VERSION 5.8 ;
BUSBITCHARS "[]" ;
DIVIDERCHAR "/" ;
UNITS
    DATABASE MICRONS 1000 ;
END UNITS

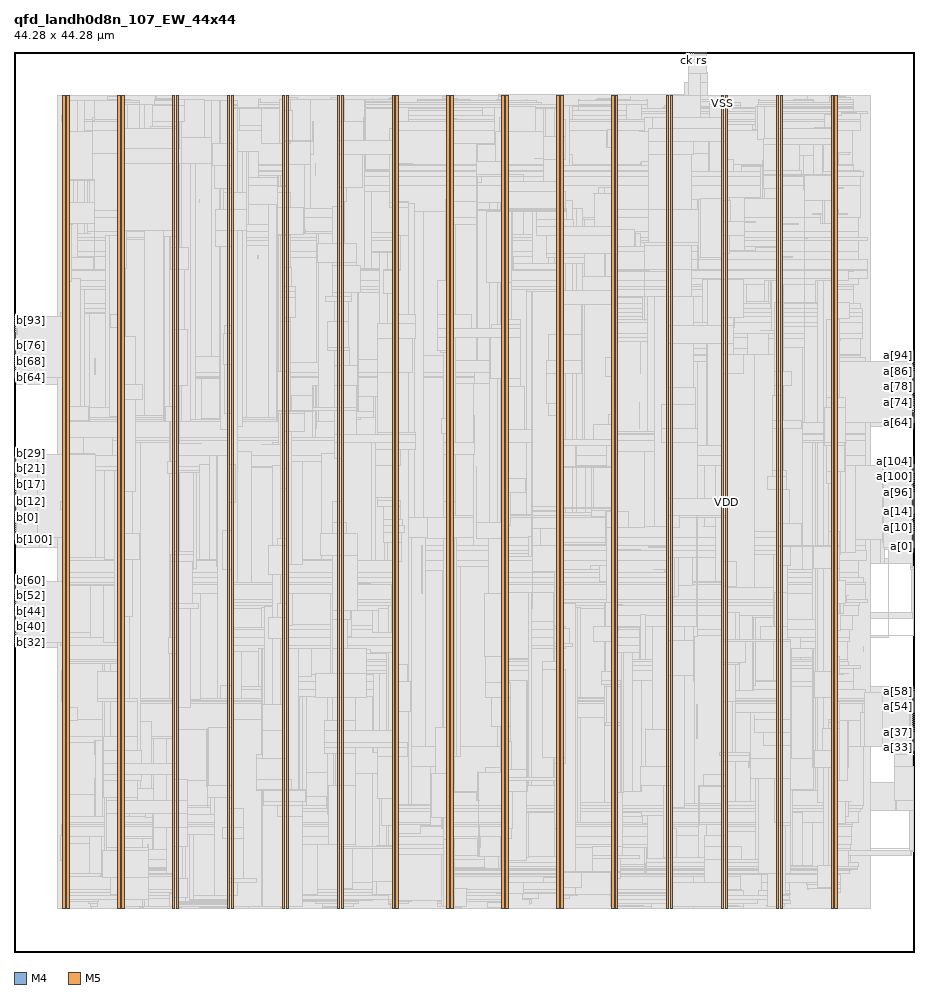
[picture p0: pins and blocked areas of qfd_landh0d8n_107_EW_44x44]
MACRO qfd_landh0d8n_107_EW_44x44
  FOREIGN qfd_landh0d8n_107_EW_44x44 0 0 ;
  CLASS BLOCK ;
  SIZE 44.28 BY 44.28 ;
  PIN a[0]
    DIRECTION INPUT ;
    USE SIGNAL ;
    PORT
      LAYER M4 ;
        RECT  44.196 19.92 44.28 19.944 ;
    END
  END a[0]
  PIN a[100]
    DIRECTION INPUT ;
    USE SIGNAL ;
    PORT
      LAYER M4 ;
        RECT  44.196 23.376 44.28 23.4 ;
    END
  END a[100]
  PIN a[101]
    DIRECTION INPUT ;
    USE SIGNAL ;
    PORT
      LAYER M4 ;
        RECT  44.196 23.472 44.28 23.496 ;
    END
  END a[101]
  PIN a[102]
    DIRECTION INPUT ;
    USE SIGNAL ;
    PORT
      LAYER M4 ;
        RECT  44.196 23.568 44.28 23.592 ;
    END
  END a[102]
  PIN a[103]
    DIRECTION INPUT ;
    USE SIGNAL ;
    PORT
      LAYER M4 ;
        RECT  44.196 23.664 44.28 23.688 ;
    END
  END a[103]
  PIN a[104]
    DIRECTION INPUT ;
    USE SIGNAL ;
    PORT
      LAYER M4 ;
        RECT  44.196 23.76 44.28 23.784 ;
    END
  END a[104]
  PIN a[105]
    DIRECTION INPUT ;
    USE SIGNAL ;
    PORT
      LAYER M4 ;
        RECT  44.196 23.856 44.28 23.88 ;
    END
  END a[105]
  PIN a[106]
    DIRECTION INPUT ;
    USE SIGNAL ;
    PORT
      LAYER M4 ;
        RECT  44.196 23.952 44.28 23.976 ;
    END
  END a[106]
  PIN a[10]
    DIRECTION INPUT ;
    USE SIGNAL ;
    PORT
      LAYER M4 ;
        RECT  44.196 20.88 44.28 20.904 ;
    END
  END a[10]
  PIN a[11]
    DIRECTION INPUT ;
    USE SIGNAL ;
    PORT
      LAYER M4 ;
        RECT  44.196 20.976 44.28 21 ;
    END
  END a[11]
  PIN a[12]
    DIRECTION INPUT ;
    USE SIGNAL ;
    PORT
      LAYER M4 ;
        RECT  44.196 21.072 44.28 21.096 ;
    END
  END a[12]
  PIN a[13]
    DIRECTION INPUT ;
    USE SIGNAL ;
    PORT
      LAYER M4 ;
        RECT  44.196 21.168 44.28 21.192 ;
    END
  END a[13]
  PIN a[14]
    DIRECTION INPUT ;
    USE SIGNAL ;
    PORT
      LAYER M4 ;
        RECT  44.196 21.264 44.28 21.288 ;
    END
  END a[14]
  PIN a[15]
    DIRECTION INPUT ;
    USE SIGNAL ;
    PORT
      LAYER M4 ;
        RECT  44.196 21.36 44.28 21.384 ;
    END
  END a[15]
  PIN a[16]
    DIRECTION INPUT ;
    USE SIGNAL ;
    PORT
      LAYER M4 ;
        RECT  44.196 21.456 44.28 21.48 ;
    END
  END a[16]
  PIN a[17]
    DIRECTION INPUT ;
    USE SIGNAL ;
    PORT
      LAYER M4 ;
        RECT  44.196 21.552 44.28 21.576 ;
    END
  END a[17]
  PIN a[18]
    DIRECTION INPUT ;
    USE SIGNAL ;
    PORT
      LAYER M4 ;
        RECT  44.196 21.648 44.28 21.672 ;
    END
  END a[18]
  PIN a[19]
    DIRECTION INPUT ;
    USE SIGNAL ;
    PORT
      LAYER M4 ;
        RECT  44.196 21.744 44.28 21.768 ;
    END
  END a[19]
  PIN a[1]
    DIRECTION INPUT ;
    USE SIGNAL ;
    PORT
      LAYER M4 ;
        RECT  44.196 20.016 44.28 20.04 ;
    END
  END a[1]
  PIN a[20]
    DIRECTION INPUT ;
    USE SIGNAL ;
    PORT
      LAYER M4 ;
        RECT  44.196 21.84 44.28 21.864 ;
    END
  END a[20]
  PIN a[21]
    DIRECTION INPUT ;
    USE SIGNAL ;
    PORT
      LAYER M4 ;
        RECT  44.196 21.936 44.28 21.96 ;
    END
  END a[21]
  PIN a[22]
    DIRECTION INPUT ;
    USE SIGNAL ;
    PORT
      LAYER M4 ;
        RECT  44.196 22.032 44.28 22.056 ;
    END
  END a[22]
  PIN a[23]
    DIRECTION INPUT ;
    USE SIGNAL ;
    PORT
      LAYER M4 ;
        RECT  44.196 22.128 44.28 22.152 ;
    END
  END a[23]
  PIN a[24]
    DIRECTION INPUT ;
    USE SIGNAL ;
    PORT
      LAYER M4 ;
        RECT  44.196 22.224 44.28 22.248 ;
    END
  END a[24]
  PIN a[25]
    DIRECTION INPUT ;
    USE SIGNAL ;
    PORT
      LAYER M4 ;
        RECT  44.196 22.32 44.28 22.344 ;
    END
  END a[25]
  PIN a[26]
    DIRECTION INPUT ;
    USE SIGNAL ;
    PORT
      LAYER M4 ;
        RECT  44.196 22.416 44.28 22.44 ;
    END
  END a[26]
  PIN a[27]
    DIRECTION INPUT ;
    USE SIGNAL ;
    PORT
      LAYER M4 ;
        RECT  44.196 22.512 44.28 22.536 ;
    END
  END a[27]
  PIN a[28]
    DIRECTION INPUT ;
    USE SIGNAL ;
    PORT
      LAYER M4 ;
        RECT  44.196 22.608 44.28 22.632 ;
    END
  END a[28]
  PIN a[29]
    DIRECTION INPUT ;
    USE SIGNAL ;
    PORT
      LAYER M4 ;
        RECT  44.196 22.704 44.28 22.728 ;
    END
  END a[29]
  PIN a[2]
    DIRECTION INPUT ;
    USE SIGNAL ;
    PORT
      LAYER M4 ;
        RECT  44.196 20.112 44.28 20.136 ;
    END
  END a[2]
  PIN a[30]
    DIRECTION INPUT ;
    USE SIGNAL ;
    PORT
      LAYER M4 ;
        RECT  44.196 22.8 44.28 22.824 ;
    END
  END a[30]
  PIN a[31]
    DIRECTION INPUT ;
    USE SIGNAL ;
    PORT
      LAYER M4 ;
        RECT  44.196 22.896 44.28 22.92 ;
    END
  END a[31]
  PIN a[32]
    DIRECTION INPUT ;
    USE SIGNAL ;
    PORT
      LAYER M4 ;
        RECT  44.196 9.936 44.28 9.96 ;
    END
  END a[32]
  PIN a[33]
    DIRECTION INPUT ;
    USE SIGNAL ;
    PORT
      LAYER M4 ;
        RECT  44.196 10.032 44.28 10.056 ;
    END
  END a[33]
  PIN a[34]
    DIRECTION INPUT ;
    USE SIGNAL ;
    PORT
      LAYER M4 ;
        RECT  44.196 10.128 44.28 10.152 ;
    END
  END a[34]
  PIN a[35]
    DIRECTION INPUT ;
    USE SIGNAL ;
    PORT
      LAYER M4 ;
        RECT  44.196 10.224 44.28 10.248 ;
    END
  END a[35]
  PIN a[36]
    DIRECTION INPUT ;
    USE SIGNAL ;
    PORT
      LAYER M4 ;
        RECT  44.196 10.32 44.28 10.344 ;
    END
  END a[36]
  PIN a[37]
    DIRECTION INPUT ;
    USE SIGNAL ;
    PORT
      LAYER M4 ;
        RECT  44.196 10.416 44.28 10.44 ;
    END
  END a[37]
  PIN a[38]
    DIRECTION INPUT ;
    USE SIGNAL ;
    PORT
      LAYER M4 ;
        RECT  44.196 10.512 44.28 10.536 ;
    END
  END a[38]
  PIN a[39]
    DIRECTION INPUT ;
    USE SIGNAL ;
    PORT
      LAYER M4 ;
        RECT  44.196 10.608 44.28 10.632 ;
    END
  END a[39]
  PIN a[3]
    DIRECTION INPUT ;
    USE SIGNAL ;
    PORT
      LAYER M4 ;
        RECT  44.196 20.208 44.28 20.232 ;
    END
  END a[3]
  PIN a[40]
    DIRECTION INPUT ;
    USE SIGNAL ;
    PORT
      LAYER M4 ;
        RECT  44.196 10.704 44.28 10.728 ;
    END
  END a[40]
  PIN a[41]
    DIRECTION INPUT ;
    USE SIGNAL ;
    PORT
      LAYER M4 ;
        RECT  44.196 10.8 44.28 10.824 ;
    END
  END a[41]
  PIN a[42]
    DIRECTION INPUT ;
    USE SIGNAL ;
    PORT
      LAYER M4 ;
        RECT  44.196 10.896 44.28 10.92 ;
    END
  END a[42]
  PIN a[43]
    DIRECTION INPUT ;
    USE SIGNAL ;
    PORT
      LAYER M4 ;
        RECT  44.196 10.992 44.28 11.016 ;
    END
  END a[43]
  PIN a[44]
    DIRECTION INPUT ;
    USE SIGNAL ;
    PORT
      LAYER M4 ;
        RECT  44.196 11.088 44.28 11.112 ;
    END
  END a[44]
  PIN a[45]
    DIRECTION INPUT ;
    USE SIGNAL ;
    PORT
      LAYER M4 ;
        RECT  44.196 11.184 44.28 11.208 ;
    END
  END a[45]
  PIN a[46]
    DIRECTION INPUT ;
    USE SIGNAL ;
    PORT
      LAYER M4 ;
        RECT  44.196 11.28 44.28 11.304 ;
    END
  END a[46]
  PIN a[47]
    DIRECTION INPUT ;
    USE SIGNAL ;
    PORT
      LAYER M4 ;
        RECT  44.196 11.376 44.28 11.4 ;
    END
  END a[47]
  PIN a[48]
    DIRECTION INPUT ;
    USE SIGNAL ;
    PORT
      LAYER M4 ;
        RECT  44.196 11.472 44.28 11.496 ;
    END
  END a[48]
  PIN a[49]
    DIRECTION INPUT ;
    USE SIGNAL ;
    PORT
      LAYER M4 ;
        RECT  44.196 11.568 44.28 11.592 ;
    END
  END a[49]
  PIN a[4]
    DIRECTION INPUT ;
    USE SIGNAL ;
    PORT
      LAYER M4 ;
        RECT  44.196 20.304 44.28 20.328 ;
    END
  END a[4]
  PIN a[50]
    DIRECTION INPUT ;
    USE SIGNAL ;
    PORT
      LAYER M4 ;
        RECT  44.196 11.664 44.28 11.688 ;
    END
  END a[50]
  PIN a[51]
    DIRECTION INPUT ;
    USE SIGNAL ;
    PORT
      LAYER M4 ;
        RECT  44.196 11.76 44.28 11.784 ;
    END
  END a[51]
  PIN a[52]
    DIRECTION INPUT ;
    USE SIGNAL ;
    PORT
      LAYER M4 ;
        RECT  44.196 11.856 44.28 11.88 ;
    END
  END a[52]
  PIN a[53]
    DIRECTION INPUT ;
    USE SIGNAL ;
    PORT
      LAYER M4 ;
        RECT  44.196 11.952 44.28 11.976 ;
    END
  END a[53]
  PIN a[54]
    DIRECTION INPUT ;
    USE SIGNAL ;
    PORT
      LAYER M4 ;
        RECT  44.196 12.048 44.28 12.072 ;
    END
  END a[54]
  PIN a[55]
    DIRECTION INPUT ;
    USE SIGNAL ;
    PORT
      LAYER M4 ;
        RECT  44.196 12.144 44.28 12.168 ;
    END
  END a[55]
  PIN a[56]
    DIRECTION INPUT ;
    USE SIGNAL ;
    PORT
      LAYER M4 ;
        RECT  44.196 12.24 44.28 12.264 ;
    END
  END a[56]
  PIN a[57]
    DIRECTION INPUT ;
    USE SIGNAL ;
    PORT
      LAYER M4 ;
        RECT  44.196 12.336 44.28 12.36 ;
    END
  END a[57]
  PIN a[58]
    DIRECTION INPUT ;
    USE SIGNAL ;
    PORT
      LAYER M4 ;
        RECT  44.196 12.432 44.28 12.456 ;
    END
  END a[58]
  PIN a[59]
    DIRECTION INPUT ;
    USE SIGNAL ;
    PORT
      LAYER M4 ;
        RECT  44.196 12.528 44.28 12.552 ;
    END
  END a[59]
  PIN a[5]
    DIRECTION INPUT ;
    USE SIGNAL ;
    PORT
      LAYER M4 ;
        RECT  44.196 20.4 44.28 20.424 ;
    END
  END a[5]
  PIN a[60]
    DIRECTION INPUT ;
    USE SIGNAL ;
    PORT
      LAYER M4 ;
        RECT  44.196 12.624 44.28 12.648 ;
    END
  END a[60]
  PIN a[61]
    DIRECTION INPUT ;
    USE SIGNAL ;
    PORT
      LAYER M4 ;
        RECT  44.196 12.72 44.28 12.744 ;
    END
  END a[61]
  PIN a[62]
    DIRECTION INPUT ;
    USE SIGNAL ;
    PORT
      LAYER M4 ;
        RECT  44.196 12.816 44.28 12.84 ;
    END
  END a[62]
  PIN a[63]
    DIRECTION INPUT ;
    USE SIGNAL ;
    PORT
      LAYER M4 ;
        RECT  44.196 12.912 44.28 12.936 ;
    END
  END a[63]
  PIN a[64]
    DIRECTION INPUT ;
    USE SIGNAL ;
    PORT
      LAYER M4 ;
        RECT  44.196 26.064 44.28 26.088 ;
    END
  END a[64]
  PIN a[65]
    DIRECTION INPUT ;
    USE SIGNAL ;
    PORT
      LAYER M4 ;
        RECT  44.196 26.16 44.28 26.184 ;
    END
  END a[65]
  PIN a[66]
    DIRECTION INPUT ;
    USE SIGNAL ;
    PORT
      LAYER M4 ;
        RECT  44.196 26.256 44.28 26.28 ;
    END
  END a[66]
  PIN a[67]
    DIRECTION INPUT ;
    USE SIGNAL ;
    PORT
      LAYER M4 ;
        RECT  44.196 26.352 44.28 26.376 ;
    END
  END a[67]
  PIN a[68]
    DIRECTION INPUT ;
    USE SIGNAL ;
    PORT
      LAYER M4 ;
        RECT  44.196 26.448 44.28 26.472 ;
    END
  END a[68]
  PIN a[69]
    DIRECTION INPUT ;
    USE SIGNAL ;
    PORT
      LAYER M4 ;
        RECT  44.196 26.544 44.28 26.568 ;
    END
  END a[69]
  PIN a[6]
    DIRECTION INPUT ;
    USE SIGNAL ;
    PORT
      LAYER M4 ;
        RECT  44.196 20.496 44.28 20.52 ;
    END
  END a[6]
  PIN a[70]
    DIRECTION INPUT ;
    USE SIGNAL ;
    PORT
      LAYER M4 ;
        RECT  44.196 26.64 44.28 26.664 ;
    END
  END a[70]
  PIN a[71]
    DIRECTION INPUT ;
    USE SIGNAL ;
    PORT
      LAYER M4 ;
        RECT  44.196 26.736 44.28 26.76 ;
    END
  END a[71]
  PIN a[72]
    DIRECTION INPUT ;
    USE SIGNAL ;
    PORT
      LAYER M4 ;
        RECT  44.196 26.832 44.28 26.856 ;
    END
  END a[72]
  PIN a[73]
    DIRECTION INPUT ;
    USE SIGNAL ;
    PORT
      LAYER M4 ;
        RECT  44.196 26.928 44.28 26.952 ;
    END
  END a[73]
  PIN a[74]
    DIRECTION INPUT ;
    USE SIGNAL ;
    PORT
      LAYER M4 ;
        RECT  44.196 27.024 44.28 27.048 ;
    END
  END a[74]
  PIN a[75]
    DIRECTION INPUT ;
    USE SIGNAL ;
    PORT
      LAYER M4 ;
        RECT  44.196 27.12 44.28 27.144 ;
    END
  END a[75]
  PIN a[76]
    DIRECTION INPUT ;
    USE SIGNAL ;
    PORT
      LAYER M4 ;
        RECT  44.196 27.216 44.28 27.24 ;
    END
  END a[76]
  PIN a[77]
    DIRECTION INPUT ;
    USE SIGNAL ;
    PORT
      LAYER M4 ;
        RECT  44.196 27.312 44.28 27.336 ;
    END
  END a[77]
  PIN a[78]
    DIRECTION INPUT ;
    USE SIGNAL ;
    PORT
      LAYER M4 ;
        RECT  44.196 27.408 44.28 27.432 ;
    END
  END a[78]
  PIN a[79]
    DIRECTION INPUT ;
    USE SIGNAL ;
    PORT
      LAYER M4 ;
        RECT  44.196 27.504 44.28 27.528 ;
    END
  END a[79]
  PIN a[7]
    DIRECTION INPUT ;
    USE SIGNAL ;
    PORT
      LAYER M4 ;
        RECT  44.196 20.592 44.28 20.616 ;
    END
  END a[7]
  PIN a[80]
    DIRECTION INPUT ;
    USE SIGNAL ;
    PORT
      LAYER M4 ;
        RECT  44.196 27.6 44.28 27.624 ;
    END
  END a[80]
  PIN a[81]
    DIRECTION INPUT ;
    USE SIGNAL ;
    PORT
      LAYER M4 ;
        RECT  44.196 27.696 44.28 27.72 ;
    END
  END a[81]
  PIN a[82]
    DIRECTION INPUT ;
    USE SIGNAL ;
    PORT
      LAYER M4 ;
        RECT  44.196 27.792 44.28 27.816 ;
    END
  END a[82]
  PIN a[83]
    DIRECTION INPUT ;
    USE SIGNAL ;
    PORT
      LAYER M4 ;
        RECT  44.196 27.888 44.28 27.912 ;
    END
  END a[83]
  PIN a[84]
    DIRECTION INPUT ;
    USE SIGNAL ;
    PORT
      LAYER M4 ;
        RECT  44.196 27.984 44.28 28.008 ;
    END
  END a[84]
  PIN a[85]
    DIRECTION INPUT ;
    USE SIGNAL ;
    PORT
      LAYER M4 ;
        RECT  44.196 28.08 44.28 28.104 ;
    END
  END a[85]
  PIN a[86]
    DIRECTION INPUT ;
    USE SIGNAL ;
    PORT
      LAYER M4 ;
        RECT  44.196 28.176 44.28 28.2 ;
    END
  END a[86]
  PIN a[87]
    DIRECTION INPUT ;
    USE SIGNAL ;
    PORT
      LAYER M4 ;
        RECT  44.196 28.272 44.28 28.296 ;
    END
  END a[87]
  PIN a[88]
    DIRECTION INPUT ;
    USE SIGNAL ;
    PORT
      LAYER M4 ;
        RECT  44.196 28.368 44.28 28.392 ;
    END
  END a[88]
  PIN a[89]
    DIRECTION INPUT ;
    USE SIGNAL ;
    PORT
      LAYER M4 ;
        RECT  44.196 28.464 44.28 28.488 ;
    END
  END a[89]
  PIN a[8]
    DIRECTION INPUT ;
    USE SIGNAL ;
    PORT
      LAYER M4 ;
        RECT  44.196 20.688 44.28 20.712 ;
    END
  END a[8]
  PIN a[90]
    DIRECTION INPUT ;
    USE SIGNAL ;
    PORT
      LAYER M4 ;
        RECT  44.196 28.56 44.28 28.584 ;
    END
  END a[90]
  PIN a[91]
    DIRECTION INPUT ;
    USE SIGNAL ;
    PORT
      LAYER M4 ;
        RECT  44.196 28.656 44.28 28.68 ;
    END
  END a[91]
  PIN a[92]
    DIRECTION INPUT ;
    USE SIGNAL ;
    PORT
      LAYER M4 ;
        RECT  44.196 28.752 44.28 28.776 ;
    END
  END a[92]
  PIN a[93]
    DIRECTION INPUT ;
    USE SIGNAL ;
    PORT
      LAYER M4 ;
        RECT  44.196 28.848 44.28 28.872 ;
    END
  END a[93]
  PIN a[94]
    DIRECTION INPUT ;
    USE SIGNAL ;
    PORT
      LAYER M4 ;
        RECT  44.196 28.944 44.28 28.968 ;
    END
  END a[94]
  PIN a[95]
    DIRECTION INPUT ;
    USE SIGNAL ;
    PORT
      LAYER M4 ;
        RECT  44.196 29.04 44.28 29.064 ;
    END
  END a[95]
  PIN a[96]
    DIRECTION INPUT ;
    USE SIGNAL ;
    PORT
      LAYER M4 ;
        RECT  44.196 22.992 44.28 23.016 ;
    END
  END a[96]
  PIN a[97]
    DIRECTION INPUT ;
    USE SIGNAL ;
    PORT
      LAYER M4 ;
        RECT  44.196 23.088 44.28 23.112 ;
    END
  END a[97]
  PIN a[98]
    DIRECTION INPUT ;
    USE SIGNAL ;
    PORT
      LAYER M4 ;
        RECT  44.196 23.184 44.28 23.208 ;
    END
  END a[98]
  PIN a[99]
    DIRECTION INPUT ;
    USE SIGNAL ;
    PORT
      LAYER M4 ;
        RECT  44.196 23.28 44.28 23.304 ;
    END
  END a[99]
  PIN a[9]
    DIRECTION INPUT ;
    USE SIGNAL ;
    PORT
      LAYER M4 ;
        RECT  44.196 20.784 44.28 20.808 ;
    END
  END a[9]
  PIN b[0]
    DIRECTION OUTPUT ;
    USE SIGNAL ;
    PORT
      LAYER M4 ;
        RECT  0 21.36 0.084 21.384 ;
    END
  END b[0]
  PIN b[100]
    DIRECTION OUTPUT ;
    USE SIGNAL ;
    PORT
      LAYER M4 ;
        RECT  0 20.688 0.084 20.712 ;
    END
  END b[100]
  PIN b[101]
    DIRECTION OUTPUT ;
    USE SIGNAL ;
    PORT
      LAYER M4 ;
        RECT  0 20.784 0.084 20.808 ;
    END
  END b[101]
  PIN b[102]
    DIRECTION OUTPUT ;
    USE SIGNAL ;
    PORT
      LAYER M4 ;
        RECT  0 20.88 0.084 20.904 ;
    END
  END b[102]
  PIN b[103]
    DIRECTION OUTPUT ;
    USE SIGNAL ;
    PORT
      LAYER M4 ;
        RECT  0 20.976 0.084 21 ;
    END
  END b[103]
  PIN b[104]
    DIRECTION OUTPUT ;
    USE SIGNAL ;
    PORT
      LAYER M4 ;
        RECT  0 21.072 0.084 21.096 ;
    END
  END b[104]
  PIN b[105]
    DIRECTION OUTPUT ;
    USE SIGNAL ;
    PORT
      LAYER M4 ;
        RECT  0 21.168 0.084 21.192 ;
    END
  END b[105]
  PIN b[106]
    DIRECTION OUTPUT ;
    USE SIGNAL ;
    PORT
      LAYER M4 ;
        RECT  0 21.264 0.084 21.288 ;
    END
  END b[106]
  PIN b[10]
    DIRECTION OUTPUT ;
    USE SIGNAL ;
    PORT
      LAYER M4 ;
        RECT  0 22.32 0.084 22.344 ;
    END
  END b[10]
  PIN b[11]
    DIRECTION OUTPUT ;
    USE SIGNAL ;
    PORT
      LAYER M4 ;
        RECT  0 22.416 0.084 22.44 ;
    END
  END b[11]
  PIN b[12]
    DIRECTION OUTPUT ;
    USE SIGNAL ;
    PORT
      LAYER M4 ;
        RECT  0 22.512 0.084 22.536 ;
    END
  END b[12]
  PIN b[13]
    DIRECTION OUTPUT ;
    USE SIGNAL ;
    PORT
      LAYER M4 ;
        RECT  0 22.608 0.084 22.632 ;
    END
  END b[13]
  PIN b[14]
    DIRECTION OUTPUT ;
    USE SIGNAL ;
    PORT
      LAYER M4 ;
        RECT  0 22.704 0.084 22.728 ;
    END
  END b[14]
  PIN b[15]
    DIRECTION OUTPUT ;
    USE SIGNAL ;
    PORT
      LAYER M4 ;
        RECT  0 22.8 0.084 22.824 ;
    END
  END b[15]
  PIN b[16]
    DIRECTION OUTPUT ;
    USE SIGNAL ;
    PORT
      LAYER M4 ;
        RECT  0 22.896 0.084 22.92 ;
    END
  END b[16]
  PIN b[17]
    DIRECTION OUTPUT ;
    USE SIGNAL ;
    PORT
      LAYER M4 ;
        RECT  0 22.992 0.084 23.016 ;
    END
  END b[17]
  PIN b[18]
    DIRECTION OUTPUT ;
    USE SIGNAL ;
    PORT
      LAYER M4 ;
        RECT  0 23.088 0.084 23.112 ;
    END
  END b[18]
  PIN b[19]
    DIRECTION OUTPUT ;
    USE SIGNAL ;
    PORT
      LAYER M4 ;
        RECT  0 23.184 0.084 23.208 ;
    END
  END b[19]
  PIN b[1]
    DIRECTION OUTPUT ;
    USE SIGNAL ;
    PORT
      LAYER M4 ;
        RECT  0 21.456 0.084 21.48 ;
    END
  END b[1]
  PIN b[20]
    DIRECTION OUTPUT ;
    USE SIGNAL ;
    PORT
      LAYER M4 ;
        RECT  0 23.28 0.084 23.304 ;
    END
  END b[20]
  PIN b[21]
    DIRECTION OUTPUT ;
    USE SIGNAL ;
    PORT
      LAYER M4 ;
        RECT  0 23.376 0.084 23.4 ;
    END
  END b[21]
  PIN b[22]
    DIRECTION OUTPUT ;
    USE SIGNAL ;
    PORT
      LAYER M4 ;
        RECT  0 23.472 0.084 23.496 ;
    END
  END b[22]
  PIN b[23]
    DIRECTION OUTPUT ;
    USE SIGNAL ;
    PORT
      LAYER M4 ;
        RECT  0 23.568 0.084 23.592 ;
    END
  END b[23]
  PIN b[24]
    DIRECTION OUTPUT ;
    USE SIGNAL ;
    PORT
      LAYER M4 ;
        RECT  0 23.664 0.084 23.688 ;
    END
  END b[24]
  PIN b[25]
    DIRECTION OUTPUT ;
    USE SIGNAL ;
    PORT
      LAYER M4 ;
        RECT  0 23.76 0.084 23.784 ;
    END
  END b[25]
  PIN b[26]
    DIRECTION OUTPUT ;
    USE SIGNAL ;
    PORT
      LAYER M4 ;
        RECT  0 23.856 0.084 23.88 ;
    END
  END b[26]
  PIN b[27]
    DIRECTION OUTPUT ;
    USE SIGNAL ;
    PORT
      LAYER M4 ;
        RECT  0 23.952 0.084 23.976 ;
    END
  END b[27]
  PIN b[28]
    DIRECTION OUTPUT ;
    USE SIGNAL ;
    PORT
      LAYER M4 ;
        RECT  0 24.048 0.084 24.072 ;
    END
  END b[28]
  PIN b[29]
    DIRECTION OUTPUT ;
    USE SIGNAL ;
    PORT
      LAYER M4 ;
        RECT  0 24.144 0.084 24.168 ;
    END
  END b[29]
  PIN b[2]
    DIRECTION OUTPUT ;
    USE SIGNAL ;
    PORT
      LAYER M4 ;
        RECT  0 21.552 0.084 21.576 ;
    END
  END b[2]
  PIN b[30]
    DIRECTION OUTPUT ;
    USE SIGNAL ;
    PORT
      LAYER M4 ;
        RECT  0 24.24 0.084 24.264 ;
    END
  END b[30]
  PIN b[31]
    DIRECTION OUTPUT ;
    USE SIGNAL ;
    PORT
      LAYER M4 ;
        RECT  0 24.336 0.084 24.36 ;
    END
  END b[31]
  PIN b[32]
    DIRECTION OUTPUT ;
    USE SIGNAL ;
    PORT
      LAYER M4 ;
        RECT  0 15.216 0.084 15.24 ;
    END
  END b[32]
  PIN b[33]
    DIRECTION OUTPUT ;
    USE SIGNAL ;
    PORT
      LAYER M4 ;
        RECT  0 15.312 0.084 15.336 ;
    END
  END b[33]
  PIN b[34]
    DIRECTION OUTPUT ;
    USE SIGNAL ;
    PORT
      LAYER M4 ;
        RECT  0 15.408 0.084 15.432 ;
    END
  END b[34]
  PIN b[35]
    DIRECTION OUTPUT ;
    USE SIGNAL ;
    PORT
      LAYER M4 ;
        RECT  0 15.504 0.084 15.528 ;
    END
  END b[35]
  PIN b[36]
    DIRECTION OUTPUT ;
    USE SIGNAL ;
    PORT
      LAYER M4 ;
        RECT  0 15.6 0.084 15.624 ;
    END
  END b[36]
  PIN b[37]
    DIRECTION OUTPUT ;
    USE SIGNAL ;
    PORT
      LAYER M4 ;
        RECT  0 15.696 0.084 15.72 ;
    END
  END b[37]
  PIN b[38]
    DIRECTION OUTPUT ;
    USE SIGNAL ;
    PORT
      LAYER M4 ;
        RECT  0 15.792 0.084 15.816 ;
    END
  END b[38]
  PIN b[39]
    DIRECTION OUTPUT ;
    USE SIGNAL ;
    PORT
      LAYER M4 ;
        RECT  0 15.888 0.084 15.912 ;
    END
  END b[39]
  PIN b[3]
    DIRECTION OUTPUT ;
    USE SIGNAL ;
    PORT
      LAYER M4 ;
        RECT  0 21.648 0.084 21.672 ;
    END
  END b[3]
  PIN b[40]
    DIRECTION OUTPUT ;
    USE SIGNAL ;
    PORT
      LAYER M4 ;
        RECT  0 15.984 0.084 16.008 ;
    END
  END b[40]
  PIN b[41]
    DIRECTION OUTPUT ;
    USE SIGNAL ;
    PORT
      LAYER M4 ;
        RECT  0 16.08 0.084 16.104 ;
    END
  END b[41]
  PIN b[42]
    DIRECTION OUTPUT ;
    USE SIGNAL ;
    PORT
      LAYER M4 ;
        RECT  0 16.176 0.084 16.2 ;
    END
  END b[42]
  PIN b[43]
    DIRECTION OUTPUT ;
    USE SIGNAL ;
    PORT
      LAYER M4 ;
        RECT  0 16.272 0.084 16.296 ;
    END
  END b[43]
  PIN b[44]
    DIRECTION OUTPUT ;
    USE SIGNAL ;
    PORT
      LAYER M4 ;
        RECT  0 16.368 0.084 16.392 ;
    END
  END b[44]
  PIN b[45]
    DIRECTION OUTPUT ;
    USE SIGNAL ;
    PORT
      LAYER M4 ;
        RECT  0 16.464 0.084 16.488 ;
    END
  END b[45]
  PIN b[46]
    DIRECTION OUTPUT ;
    USE SIGNAL ;
    PORT
      LAYER M4 ;
        RECT  0 16.56 0.084 16.584 ;
    END
  END b[46]
  PIN b[47]
    DIRECTION OUTPUT ;
    USE SIGNAL ;
    PORT
      LAYER M4 ;
        RECT  0 16.656 0.084 16.68 ;
    END
  END b[47]
  PIN b[48]
    DIRECTION OUTPUT ;
    USE SIGNAL ;
    PORT
      LAYER M4 ;
        RECT  0 16.752 0.084 16.776 ;
    END
  END b[48]
  PIN b[49]
    DIRECTION OUTPUT ;
    USE SIGNAL ;
    PORT
      LAYER M4 ;
        RECT  0 16.848 0.084 16.872 ;
    END
  END b[49]
  PIN b[4]
    DIRECTION OUTPUT ;
    USE SIGNAL ;
    PORT
      LAYER M4 ;
        RECT  0 21.744 0.084 21.768 ;
    END
  END b[4]
  PIN b[50]
    DIRECTION OUTPUT ;
    USE SIGNAL ;
    PORT
      LAYER M4 ;
        RECT  0 16.944 0.084 16.968 ;
    END
  END b[50]
  PIN b[51]
    DIRECTION OUTPUT ;
    USE SIGNAL ;
    PORT
      LAYER M4 ;
        RECT  0 17.04 0.084 17.064 ;
    END
  END b[51]
  PIN b[52]
    DIRECTION OUTPUT ;
    USE SIGNAL ;
    PORT
      LAYER M4 ;
        RECT  0 17.136 0.084 17.16 ;
    END
  END b[52]
  PIN b[53]
    DIRECTION OUTPUT ;
    USE SIGNAL ;
    PORT
      LAYER M4 ;
        RECT  0 17.232 0.084 17.256 ;
    END
  END b[53]
  PIN b[54]
    DIRECTION OUTPUT ;
    USE SIGNAL ;
    PORT
      LAYER M4 ;
        RECT  0 17.328 0.084 17.352 ;
    END
  END b[54]
  PIN b[55]
    DIRECTION OUTPUT ;
    USE SIGNAL ;
    PORT
      LAYER M4 ;
        RECT  0 17.424 0.084 17.448 ;
    END
  END b[55]
  PIN b[56]
    DIRECTION OUTPUT ;
    USE SIGNAL ;
    PORT
      LAYER M4 ;
        RECT  0 17.52 0.084 17.544 ;
    END
  END b[56]
  PIN b[57]
    DIRECTION OUTPUT ;
    USE SIGNAL ;
    PORT
      LAYER M4 ;
        RECT  0 17.616 0.084 17.64 ;
    END
  END b[57]
  PIN b[58]
    DIRECTION OUTPUT ;
    USE SIGNAL ;
    PORT
      LAYER M4 ;
        RECT  0 17.712 0.084 17.736 ;
    END
  END b[58]
  PIN b[59]
    DIRECTION OUTPUT ;
    USE SIGNAL ;
    PORT
      LAYER M4 ;
        RECT  0 17.808 0.084 17.832 ;
    END
  END b[59]
  PIN b[5]
    DIRECTION OUTPUT ;
    USE SIGNAL ;
    PORT
      LAYER M4 ;
        RECT  0 21.84 0.084 21.864 ;
    END
  END b[5]
  PIN b[60]
    DIRECTION OUTPUT ;
    USE SIGNAL ;
    PORT
      LAYER M4 ;
        RECT  0 17.904 0.084 17.928 ;
    END
  END b[60]
  PIN b[61]
    DIRECTION OUTPUT ;
    USE SIGNAL ;
    PORT
      LAYER M4 ;
        RECT  0 18 0.084 18.024 ;
    END
  END b[61]
  PIN b[62]
    DIRECTION OUTPUT ;
    USE SIGNAL ;
    PORT
      LAYER M4 ;
        RECT  0 18.096 0.084 18.12 ;
    END
  END b[62]
  PIN b[63]
    DIRECTION OUTPUT ;
    USE SIGNAL ;
    PORT
      LAYER M4 ;
        RECT  0 18.192 0.084 18.216 ;
    END
  END b[63]
  PIN b[64]
    DIRECTION OUTPUT ;
    USE SIGNAL ;
    PORT
      LAYER M4 ;
        RECT  0 28.272 0.084 28.296 ;
    END
  END b[64]
  PIN b[65]
    DIRECTION OUTPUT ;
    USE SIGNAL ;
    PORT
      LAYER M4 ;
        RECT  0 28.368 0.084 28.392 ;
    END
  END b[65]
  PIN b[66]
    DIRECTION OUTPUT ;
    USE SIGNAL ;
    PORT
      LAYER M4 ;
        RECT  0 28.464 0.084 28.488 ;
    END
  END b[66]
  PIN b[67]
    DIRECTION OUTPUT ;
    USE SIGNAL ;
    PORT
      LAYER M4 ;
        RECT  0 28.56 0.084 28.584 ;
    END
  END b[67]
  PIN b[68]
    DIRECTION OUTPUT ;
    USE SIGNAL ;
    PORT
      LAYER M4 ;
        RECT  0 28.656 0.084 28.68 ;
    END
  END b[68]
  PIN b[69]
    DIRECTION OUTPUT ;
    USE SIGNAL ;
    PORT
      LAYER M4 ;
        RECT  0 28.752 0.084 28.776 ;
    END
  END b[69]
  PIN b[6]
    DIRECTION OUTPUT ;
    USE SIGNAL ;
    PORT
      LAYER M4 ;
        RECT  0 21.936 0.084 21.96 ;
    END
  END b[6]
  PIN b[70]
    DIRECTION OUTPUT ;
    USE SIGNAL ;
    PORT
      LAYER M4 ;
        RECT  0 28.848 0.084 28.872 ;
    END
  END b[70]
  PIN b[71]
    DIRECTION OUTPUT ;
    USE SIGNAL ;
    PORT
      LAYER M4 ;
        RECT  0 28.944 0.084 28.968 ;
    END
  END b[71]
  PIN b[72]
    DIRECTION OUTPUT ;
    USE SIGNAL ;
    PORT
      LAYER M4 ;
        RECT  0 29.04 0.084 29.064 ;
    END
  END b[72]
  PIN b[73]
    DIRECTION OUTPUT ;
    USE SIGNAL ;
    PORT
      LAYER M4 ;
        RECT  0 29.136 0.084 29.16 ;
    END
  END b[73]
  PIN b[74]
    DIRECTION OUTPUT ;
    USE SIGNAL ;
    PORT
      LAYER M4 ;
        RECT  0 29.232 0.084 29.256 ;
    END
  END b[74]
  PIN b[75]
    DIRECTION OUTPUT ;
    USE SIGNAL ;
    PORT
      LAYER M4 ;
        RECT  0 29.328 0.084 29.352 ;
    END
  END b[75]
  PIN b[76]
    DIRECTION OUTPUT ;
    USE SIGNAL ;
    PORT
      LAYER M4 ;
        RECT  0 29.424 0.084 29.448 ;
    END
  END b[76]
  PIN b[77]
    DIRECTION OUTPUT ;
    USE SIGNAL ;
    PORT
      LAYER M4 ;
        RECT  0 29.52 0.084 29.544 ;
    END
  END b[77]
  PIN b[78]
    DIRECTION OUTPUT ;
    USE SIGNAL ;
    PORT
      LAYER M4 ;
        RECT  0 29.616 0.084 29.64 ;
    END
  END b[78]
  PIN b[79]
    DIRECTION OUTPUT ;
    USE SIGNAL ;
    PORT
      LAYER M4 ;
        RECT  0 29.712 0.084 29.736 ;
    END
  END b[79]
  PIN b[7]
    DIRECTION OUTPUT ;
    USE SIGNAL ;
    PORT
      LAYER M4 ;
        RECT  0 22.032 0.084 22.056 ;
    END
  END b[7]
  PIN b[80]
    DIRECTION OUTPUT ;
    USE SIGNAL ;
    PORT
      LAYER M4 ;
        RECT  0 29.808 0.084 29.832 ;
    END
  END b[80]
  PIN b[81]
    DIRECTION OUTPUT ;
    USE SIGNAL ;
    PORT
      LAYER M4 ;
        RECT  0 29.904 0.084 29.928 ;
    END
  END b[81]
  PIN b[82]
    DIRECTION OUTPUT ;
    USE SIGNAL ;
    PORT
      LAYER M4 ;
        RECT  0 30 0.084 30.024 ;
    END
  END b[82]
  PIN b[83]
    DIRECTION OUTPUT ;
    USE SIGNAL ;
    PORT
      LAYER M4 ;
        RECT  0 30.096 0.084 30.12 ;
    END
  END b[83]
  PIN b[84]
    DIRECTION OUTPUT ;
    USE SIGNAL ;
    PORT
      LAYER M4 ;
        RECT  0 30.192 0.084 30.216 ;
    END
  END b[84]
  PIN b[85]
    DIRECTION OUTPUT ;
    USE SIGNAL ;
    PORT
      LAYER M4 ;
        RECT  0 30.288 0.084 30.312 ;
    END
  END b[85]
  PIN b[86]
    DIRECTION OUTPUT ;
    USE SIGNAL ;
    PORT
      LAYER M4 ;
        RECT  0 30.384 0.084 30.408 ;
    END
  END b[86]
  PIN b[87]
    DIRECTION OUTPUT ;
    USE SIGNAL ;
    PORT
      LAYER M4 ;
        RECT  0 30.48 0.084 30.504 ;
    END
  END b[87]
  PIN b[88]
    DIRECTION OUTPUT ;
    USE SIGNAL ;
    PORT
      LAYER M4 ;
        RECT  0 30.576 0.084 30.6 ;
    END
  END b[88]
  PIN b[89]
    DIRECTION OUTPUT ;
    USE SIGNAL ;
    PORT
      LAYER M4 ;
        RECT  0 30.672 0.084 30.696 ;
    END
  END b[89]
  PIN b[8]
    DIRECTION OUTPUT ;
    USE SIGNAL ;
    PORT
      LAYER M4 ;
        RECT  0 22.128 0.084 22.152 ;
    END
  END b[8]
  PIN b[90]
    DIRECTION OUTPUT ;
    USE SIGNAL ;
    PORT
      LAYER M4 ;
        RECT  0 30.768 0.084 30.792 ;
    END
  END b[90]
  PIN b[91]
    DIRECTION OUTPUT ;
    USE SIGNAL ;
    PORT
      LAYER M4 ;
        RECT  0 30.864 0.084 30.888 ;
    END
  END b[91]
  PIN b[92]
    DIRECTION OUTPUT ;
    USE SIGNAL ;
    PORT
      LAYER M4 ;
        RECT  0 30.96 0.084 30.984 ;
    END
  END b[92]
  PIN b[93]
    DIRECTION OUTPUT ;
    USE SIGNAL ;
    PORT
      LAYER M4 ;
        RECT  0 31.056 0.084 31.08 ;
    END
  END b[93]
  PIN b[94]
    DIRECTION OUTPUT ;
    USE SIGNAL ;
    PORT
      LAYER M4 ;
        RECT  0 31.152 0.084 31.176 ;
    END
  END b[94]
  PIN b[95]
    DIRECTION OUTPUT ;
    USE SIGNAL ;
    PORT
      LAYER M4 ;
        RECT  0 31.248 0.084 31.272 ;
    END
  END b[95]
  PIN b[96]
    DIRECTION OUTPUT ;
    USE SIGNAL ;
    PORT
      LAYER M4 ;
        RECT  0 20.304 0.084 20.328 ;
    END
  END b[96]
  PIN b[97]
    DIRECTION OUTPUT ;
    USE SIGNAL ;
    PORT
      LAYER M4 ;
        RECT  0 20.4 0.084 20.424 ;
    END
  END b[97]
  PIN b[98]
    DIRECTION OUTPUT ;
    USE SIGNAL ;
    PORT
      LAYER M4 ;
        RECT  0 20.496 0.084 20.52 ;
    END
  END b[98]
  PIN b[99]
    DIRECTION OUTPUT ;
    USE SIGNAL ;
    PORT
      LAYER M4 ;
        RECT  0 20.592 0.084 20.616 ;
    END
  END b[99]
  PIN b[9]
    DIRECTION OUTPUT ;
    USE SIGNAL ;
    PORT
      LAYER M4 ;
        RECT  0 22.224 0.084 22.248 ;
    END
  END b[9]
  PIN ck
    DIRECTION INPUT ;
    USE SIGNAL ;
    PORT
      LAYER M5 ;
        RECT  33.072 44.196 33.096 44.28 ;
    END
  END ck
  PIN ck_s
    DIRECTION INPUT ;
    USE SIGNAL ;
    PORT
      LAYER M5 ;
        RECT  33.168 44.196 33.192 44.28 ;
    END
  END ck_s
  PIN en
    DIRECTION INPUT ;
    USE SIGNAL ;
    PORT
      LAYER M5 ;
        RECT  33.264 44.196 33.288 44.28 ;
    END
  END en
  PIN fault
    DIRECTION OUTPUT ;
    USE SIGNAL ;
    PORT
      LAYER M5 ;
        RECT  33.36 44.196 33.384 44.28 ;
    END
  END fault
  PIN k0
    DIRECTION INPUT ;
    USE SIGNAL ;
    PORT
      LAYER M5 ;
        RECT  33.456 44.196 33.48 44.28 ;
    END
  END k0
  PIN k1
    DIRECTION INPUT ;
    USE SIGNAL ;
    PORT
      LAYER M5 ;
        RECT  33.552 44.196 33.576 44.28 ;
    END
  END k1
  PIN k2
    DIRECTION INPUT ;
    USE SIGNAL ;
    PORT
      LAYER M5 ;
        RECT  33.648 44.196 33.672 44.28 ;
    END
  END k2
  PIN k3
    DIRECTION INPUT ;
    USE SIGNAL ;
    PORT
      LAYER M5 ;
        RECT  33.744 44.196 33.768 44.28 ;
    END
  END k3
  PIN rs
    DIRECTION INPUT ;
    USE SIGNAL ;
    PORT
      LAYER M5 ;
        RECT  33.84 44.196 33.864 44.28 ;
    END
  END rs
  PIN tie_hi
    DIRECTION OUTPUT ;
    USE SIGNAL ;
    PORT
      LAYER M5 ;
        RECT  33.936 44.196 33.96 44.28 ;
    END
  END tie_hi
  PIN tie_lo
    DIRECTION OUTPUT ;
    USE SIGNAL ;
    PORT
      LAYER M5 ;
        RECT  34.032 44.196 34.056 44.28 ;
    END
  END tie_lo
  PIN VSS
    DIRECTION INOUT ;
    USE GROUND ;
    PORT
      LAYER M5 ;
        RECT  40.2 2.137 40.32 42.143 ;
        RECT  37.5 2.137 37.62 42.143 ;
        RECT  34.8 2.137 34.92 42.143 ;
        RECT  32.1 2.137 32.22 42.143 ;
        RECT  29.4 2.137 29.52 42.143 ;
        RECT  26.7 2.137 26.82 42.143 ;
        RECT  24 2.137 24.12 42.143 ;
        RECT  21.3 2.137 21.42 42.143 ;
        RECT  18.6 2.137 18.72 42.143 ;
        RECT  15.9 2.137 16.02 42.143 ;
        RECT  13.2 2.137 13.32 42.143 ;
        RECT  10.5 2.137 10.62 42.143 ;
        RECT  7.8 2.137 7.92 42.143 ;
        RECT  5.1 2.137 5.22 42.143 ;
        RECT  2.4 2.137 2.52 42.143 ;
    END
  END VSS
  PIN VDD
    DIRECTION INOUT ;
    USE POWER ;
    PORT
      LAYER M5 ;
        RECT  40.392 2.151 40.512 42.129 ;
        RECT  37.692 2.151 37.812 42.129 ;
        RECT  34.992 2.151 35.112 42.129 ;
        RECT  32.292 2.151 32.412 42.129 ;
        RECT  29.592 2.151 29.712 42.129 ;
        RECT  26.892 2.151 27.012 42.129 ;
        RECT  24.192 2.151 24.312 42.129 ;
        RECT  21.492 2.151 21.612 42.129 ;
        RECT  18.792 2.151 18.912 42.129 ;
        RECT  16.092 2.151 16.212 42.129 ;
        RECT  13.392 2.151 13.512 42.129 ;
        RECT  10.692 2.151 10.812 42.129 ;
        RECT  7.992 2.151 8.112 42.129 ;
        RECT  5.292 2.151 5.412 42.129 ;
        RECT  2.592 2.151 2.712 42.129 ;
    END
  END VDD
  OBS
    LAYER RVTN ;
     RECT  2.16 2.16 42.12 2.295 ;
     RECT  2.16 2.565 42.12 2.835 ;
     RECT  2.16 3.105 42.12 3.375 ;
     RECT  2.16 3.645 42.12 3.915 ;
     RECT  2.16 4.185 42.12 4.455 ;
     RECT  2.16 4.725 42.12 4.995 ;
     RECT  2.16 5.265 42.12 5.535 ;
     RECT  2.16 5.805 42.12 6.075 ;
     RECT  2.16 6.345 42.12 6.615 ;
     RECT  2.16 6.885 42.12 7.155 ;
     RECT  2.16 7.425 42.12 7.695 ;
     RECT  2.16 7.965 42.12 8.235 ;
     RECT  2.16 8.505 42.12 8.775 ;
     RECT  2.16 9.045 42.12 9.315 ;
     RECT  2.16 9.585 42.12 9.855 ;
     RECT  2.16 10.125 42.12 10.395 ;
     RECT  2.16 10.665 42.12 10.935 ;
     RECT  2.16 11.205 42.12 11.475 ;
     RECT  2.16 11.745 42.12 12.015 ;
     RECT  2.16 12.285 42.12 12.555 ;
     RECT  2.16 12.825 42.12 13.095 ;
     RECT  2.16 13.365 42.12 13.635 ;
     RECT  2.16 13.905 42.12 14.175 ;
     RECT  2.16 14.445 42.12 14.715 ;
     RECT  2.16 14.985 42.12 15.255 ;
     RECT  2.16 15.525 42.12 15.795 ;
     RECT  2.16 16.065 42.12 16.335 ;
     RECT  2.16 16.605 42.12 16.875 ;
     RECT  2.16 17.145 42.12 17.415 ;
     RECT  2.16 17.685 42.12 17.955 ;
     RECT  2.16 18.225 42.12 18.495 ;
     RECT  2.16 18.765 42.12 19.035 ;
     RECT  2.16 19.305 42.12 19.575 ;
     RECT  2.16 19.845 42.12 20.115 ;
     RECT  2.16 20.385 42.12 20.655 ;
     RECT  2.16 20.925 42.12 21.195 ;
     RECT  2.16 21.465 42.12 21.735 ;
     RECT  2.16 22.005 42.12 22.275 ;
     RECT  2.16 22.545 42.12 22.815 ;
     RECT  2.16 23.085 42.12 23.355 ;
     RECT  2.16 23.625 42.12 23.895 ;
     RECT  2.16 24.165 42.12 24.435 ;
     RECT  2.16 24.705 42.12 24.975 ;
     RECT  2.16 25.245 42.12 25.515 ;
     RECT  2.16 25.785 42.12 26.055 ;
     RECT  2.16 26.325 42.12 26.595 ;
     RECT  2.16 26.865 42.12 27.135 ;
     RECT  2.16 27.405 42.12 27.675 ;
     RECT  2.16 27.945 42.12 28.215 ;
     RECT  2.16 28.485 42.12 28.755 ;
     RECT  2.16 29.025 42.12 29.295 ;
     RECT  2.16 29.565 42.12 29.835 ;
     RECT  2.16 30.105 42.12 30.375 ;
     RECT  2.16 30.645 42.12 30.915 ;
     RECT  2.16 31.185 42.12 31.455 ;
     RECT  2.16 31.725 42.12 31.995 ;
     RECT  2.16 32.265 42.12 32.535 ;
     RECT  2.16 32.805 42.12 33.075 ;
     RECT  2.16 33.345 42.12 33.615 ;
     RECT  2.16 33.885 42.12 34.155 ;
     RECT  2.16 34.425 42.12 34.695 ;
     RECT  2.16 34.965 42.12 35.235 ;
     RECT  2.16 35.505 42.12 35.775 ;
     RECT  2.16 36.045 42.12 36.315 ;
     RECT  2.16 36.585 42.12 36.855 ;
     RECT  2.16 37.125 42.12 37.395 ;
     RECT  2.16 37.665 42.12 37.935 ;
     RECT  2.16 38.205 42.12 38.475 ;
     RECT  2.16 38.745 42.12 39.015 ;
     RECT  2.16 39.285 42.12 39.555 ;
     RECT  2.16 39.825 42.12 40.095 ;
     RECT  2.16 40.365 42.12 40.635 ;
     RECT  2.16 40.905 42.12 41.175 ;
     RECT  2.16 41.445 42.12 41.715 ;
     RECT  2.16 41.985 42.12 42.12 ;
    LAYER RVTP ;
     RECT  2.16 2.295 42.12 2.565 ;
     RECT  2.16 2.835 42.12 3.105 ;
     RECT  2.16 3.375 42.12 3.645 ;
     RECT  2.16 3.915 42.12 4.185 ;
     RECT  2.16 4.455 42.12 4.725 ;
     RECT  2.16 4.995 42.12 5.265 ;
     RECT  2.16 5.535 42.12 5.805 ;
     RECT  2.16 6.075 42.12 6.345 ;
     RECT  2.16 6.615 42.12 6.885 ;
     RECT  2.16 7.155 42.12 7.425 ;
     RECT  2.16 7.695 42.12 7.965 ;
     RECT  2.16 8.235 42.12 8.505 ;
     RECT  2.16 8.775 42.12 9.045 ;
     RECT  2.16 9.315 42.12 9.585 ;
     RECT  2.16 9.855 42.12 10.125 ;
     RECT  2.16 10.395 42.12 10.665 ;
     RECT  2.16 10.935 42.12 11.205 ;
     RECT  2.16 11.475 42.12 11.745 ;
     RECT  2.16 12.015 42.12 12.285 ;
     RECT  2.16 12.555 42.12 12.825 ;
     RECT  2.16 13.095 42.12 13.365 ;
     RECT  2.16 13.635 42.12 13.905 ;
     RECT  2.16 14.175 42.12 14.445 ;
     RECT  2.16 14.715 42.12 14.985 ;
     RECT  2.16 15.255 42.12 15.525 ;
     RECT  2.16 15.795 42.12 16.065 ;
     RECT  2.16 16.335 42.12 16.605 ;
     RECT  2.16 16.875 42.12 17.145 ;
     RECT  2.16 17.415 42.12 17.685 ;
     RECT  2.16 17.955 42.12 18.225 ;
     RECT  2.16 18.495 42.12 18.765 ;
     RECT  2.16 19.035 42.12 19.305 ;
     RECT  2.16 19.575 42.12 19.845 ;
     RECT  2.16 20.115 42.12 20.385 ;
     RECT  2.16 20.655 42.12 20.925 ;
     RECT  2.16 21.195 42.12 21.465 ;
     RECT  2.16 21.735 42.12 22.005 ;
     RECT  2.16 22.275 42.12 22.545 ;
     RECT  2.16 22.815 42.12 23.085 ;
     RECT  2.16 23.355 42.12 23.625 ;
     RECT  2.16 23.895 42.12 24.165 ;
     RECT  2.16 24.435 42.12 24.705 ;
     RECT  2.16 24.975 42.12 25.245 ;
     RECT  2.16 25.515 42.12 25.785 ;
     RECT  2.16 26.055 42.12 26.325 ;
     RECT  2.16 26.595 42.12 26.865 ;
     RECT  2.16 27.135 42.12 27.405 ;
     RECT  2.16 27.675 42.12 27.945 ;
     RECT  2.16 28.215 42.12 28.485 ;
     RECT  2.16 28.755 42.12 29.025 ;
     RECT  2.16 29.295 42.12 29.565 ;
     RECT  2.16 29.835 42.12 30.105 ;
     RECT  2.16 30.375 42.12 30.645 ;
     RECT  2.16 30.915 42.12 31.185 ;
     RECT  2.16 31.455 42.12 31.725 ;
     RECT  2.16 31.995 42.12 32.265 ;
     RECT  2.16 32.535 42.12 32.805 ;
     RECT  2.16 33.075 42.12 33.345 ;
     RECT  2.16 33.615 42.12 33.885 ;
     RECT  2.16 34.155 42.12 34.425 ;
     RECT  2.16 34.695 42.12 34.965 ;
     RECT  2.16 35.235 42.12 35.505 ;
     RECT  2.16 35.775 42.12 36.045 ;
     RECT  2.16 36.315 42.12 36.585 ;
     RECT  2.16 36.855 42.12 37.125 ;
     RECT  2.16 37.395 42.12 37.665 ;
     RECT  2.16 37.935 42.12 38.205 ;
     RECT  2.16 38.475 42.12 38.745 ;
     RECT  2.16 39.015 42.12 39.285 ;
     RECT  2.16 39.555 42.12 39.825 ;
     RECT  2.16 40.095 42.12 40.365 ;
     RECT  2.16 40.635 42.12 40.905 ;
     RECT  2.16 41.175 42.12 41.445 ;
     RECT  2.16 41.715 42.12 41.985 ;
    LAYER M1 ;
     RECT  2.16 2.151 42.12 42.129 ;
    LAYER M2 ;
     RECT  0.103 30.231 0.139 30.249 ;
     RECT  0.139 30.231 0.203 30.474 ;
     RECT  0.203 30.456 0.239 30.474 ;
     RECT  0.103 27.918 0.463 27.936 ;
     RECT  0.103 29.034 0.463 29.052 ;
     RECT  0.499 15.264 0.535 15.282 ;
     RECT  0.103 19.926 0.535 20.484 ;
     RECT  0.499 21.636 0.535 22.914 ;
     RECT  0.535 19.926 0.599 23.346 ;
     RECT  0.599 19.926 1.247 22.374 ;
     RECT  0.535 14.994 2.16 15.282 ;
     RECT  0.535 16.344 2.16 16.362 ;
     RECT  1.247 19.926 2.16 21.564 ;
     RECT  1.247 22.356 2.16 22.374 ;
     RECT  0.599 23.328 2.16 23.346 ;
     RECT  0.463 27.918 2.16 29.052 ;
     RECT  2.16 2.151 23.827 42.129 ;
     RECT  23.827 2.151 33.431 42.174 ;
     RECT  33.431 2.151 42.12 42.129 ;
     RECT  42.12 19.116 42.611 23.454 ;
     RECT  42.611 21.978 42.791 23.454 ;
     RECT  42.611 19.116 42.827 21.024 ;
     RECT  42.12 15.498 43.043 15.588 ;
     RECT  42.12 6.966 43.367 8.334 ;
     RECT  42.12 10.44 43.367 13.086 ;
     RECT  42.827 19.116 43.367 19.368 ;
     RECT  42.791 22.32 43.367 23.454 ;
     RECT  42.12 25.866 43.367 26.424 ;
     RECT  42.12 27.378 43.367 28.584 ;
     RECT  43.367 8.046 43.403 8.334 ;
     RECT  43.367 10.674 43.403 11.304 ;
     RECT  43.367 19.116 43.403 19.332 ;
     RECT  43.367 27.378 43.403 27.504 ;
     RECT  43.367 6.966 43.439 6.984 ;
     RECT  43.403 10.674 43.439 11.196 ;
     RECT  43.403 19.116 43.439 19.134 ;
     RECT  43.367 22.356 43.439 23.454 ;
     RECT  43.403 27.378 43.439 27.396 ;
     RECT  43.403 8.046 43.475 8.064 ;
     RECT  43.439 10.674 43.475 10.692 ;
     RECT  42.827 20.196 43.475 21.024 ;
     RECT  43.439 22.401 43.475 22.419 ;
     RECT  43.439 23.436 43.475 23.454 ;
     RECT  43.475 20.394 43.511 21.024 ;
     RECT  43.511 21.006 43.583 21.024 ;
     RECT  42.12 16.416 44.195 16.704 ;
     RECT  44.095 18.81 44.195 18.954 ;
     RECT  42.12 5.076 44.231 5.094 ;
     RECT  44.195 16.416 44.231 16.434 ;
     RECT  44.195 18.891 44.231 18.954 ;
     RECT  44.167 9.09 44.267 9.108 ;
     RECT  43.043 15.57 44.267 15.588 ;
     RECT  44.231 18.891 44.267 18.909 ;
     RECT  44.167 23.94 44.267 23.958 ;
     RECT  44.167 26.532 44.267 26.82 ;
    LAYER M3 ;
     RECT  7.815 2.143 7.905 2.191 ;
     RECT  10.515 2.143 10.605 2.191 ;
     RECT  13.215 2.143 13.305 2.191 ;
     RECT  15.915 2.143 16.005 2.191 ;
     RECT  18.615 2.143 18.705 2.191 ;
     RECT  21.315 2.143 21.405 2.191 ;
     RECT  24.015 2.143 24.105 2.191 ;
     RECT  29.415 2.143 29.505 2.191 ;
     RECT  34.815 2.143 34.905 2.191 ;
     RECT  5.115 2.143 5.205 2.227 ;
     RECT  6.192 2.191 6.354 2.227 ;
     RECT  7.815 2.191 8.226 2.227 ;
     RECT  15.156 2.191 16.005 2.227 ;
     RECT  29.415 2.191 29.574 2.227 ;
     RECT  37.515 2.143 37.605 2.227 ;
     RECT  21.315 2.191 22.014 2.24 ;
     RECT  21.024 2.24 22.014 2.251 ;
     RECT  29.415 2.227 30.258 2.251 ;
     RECT  31.356 2.191 31.374 2.251 ;
     RECT  34.815 2.191 34.974 2.251 ;
     RECT  35.892 2.191 35.91 2.251 ;
     RECT  3.816 2.191 3.834 2.263 ;
     RECT  7.272 2.227 8.226 2.263 ;
     RECT  9.144 2.191 10.605 2.263 ;
     RECT  21.024 2.251 22.23 2.263 ;
     RECT  32.115 2.143 32.205 2.263 ;
     RECT  33.084 2.227 33.102 2.263 ;
     RECT  37.404 2.227 37.605 2.263 ;
     RECT  11.52 2.191 11.538 2.299 ;
     RECT  6.048 2.227 6.354 2.335 ;
     RECT  7.272 2.263 10.605 2.335 ;
     RECT  11.52 2.299 11.718 2.335 ;
     RECT  13.104 2.191 13.305 2.335 ;
     RECT  18.54 2.191 18.705 2.335 ;
     RECT  3.744 2.263 4.086 2.371 ;
     RECT  6.048 2.335 13.554 2.371 ;
     RECT  15.156 2.227 16.686 2.371 ;
     RECT  18.432 2.335 18.705 2.371 ;
     RECT  20.844 2.263 22.23 2.371 ;
     RECT  25.344 2.335 25.362 2.371 ;
     RECT  29.376 2.251 31.374 2.371 ;
     RECT  32.115 2.263 33.426 2.371 ;
     RECT  34.308 2.251 35.91 2.371 ;
     RECT  37.404 2.263 37.926 2.371 ;
     RECT  2.415 2.143 2.505 2.413 ;
     RECT  5.115 2.227 5.274 2.413 ;
     RECT  6.048 2.371 14.058 2.413 ;
     RECT  23.292 2.191 24.105 2.413 ;
     RECT  26.715 2.143 26.805 2.413 ;
     RECT  40.215 2.143 40.305 2.413 ;
     RECT  2.415 2.413 2.697 2.461 ;
     RECT  3.672 2.371 4.122 2.461 ;
     RECT  18.432 2.371 19.422 2.461 ;
     RECT  20.844 2.371 22.266 2.461 ;
     RECT  23.292 2.413 24.297 2.461 ;
     RECT  2.415 2.461 4.122 2.497 ;
     RECT  5.115 2.413 14.058 2.497 ;
     RECT  14.832 2.371 16.938 2.497 ;
     RECT  37.404 2.371 38.214 2.525 ;
     RECT  5.115 2.497 16.938 2.533 ;
     RECT  2.415 2.497 4.158 2.569 ;
     RECT  5.115 2.533 17.658 2.569 ;
     RECT  18.432 2.461 19.566 2.569 ;
     RECT  29.376 2.371 36.594 2.569 ;
     RECT  37.404 2.525 38.178 2.569 ;
     RECT  2.415 2.569 17.658 2.605 ;
     RECT  18.432 2.569 19.818 2.605 ;
     RECT  20.844 2.461 24.297 2.605 ;
     RECT  25.344 2.371 25.47 2.605 ;
     RECT  25.02 2.605 25.47 2.641 ;
     RECT  26.715 2.413 26.997 2.641 ;
     RECT  29.376 2.569 38.178 2.759 ;
     RECT  2.415 2.605 19.818 2.767 ;
     RECT  20.808 2.605 24.297 2.767 ;
     RECT  26.715 2.641 27.306 2.803 ;
     RECT  29.376 2.759 33.462 2.803 ;
     RECT  26.715 2.803 27.702 2.827 ;
     RECT  25.02 2.641 25.794 2.875 ;
     RECT  26.715 2.827 27.918 2.875 ;
     RECT  29.304 2.803 33.462 2.875 ;
     RECT  29.232 2.875 33.462 2.903 ;
     RECT  2.415 2.767 19.962 2.911 ;
     RECT  20.7 2.767 24.297 2.911 ;
     RECT  25.02 2.875 27.918 2.911 ;
     RECT  40.215 2.413 40.497 2.911 ;
     RECT  34.2 2.759 35.91 3.029 ;
     RECT  36.648 2.759 38.178 3.029 ;
     RECT  34.2 3.029 35.802 3.065 ;
     RECT  2.415 2.911 28.35 3.073 ;
     RECT  29.232 2.903 33.426 3.073 ;
     RECT  39.06 3.073 39.078 3.145 ;
     RECT  40.215 2.911 40.662 3.145 ;
     RECT  39.06 3.145 40.662 3.343 ;
     RECT  36.756 3.029 38.178 3.415 ;
     RECT  38.988 3.343 40.662 3.415 ;
     RECT  2.415 3.073 33.426 3.721 ;
     RECT  34.2 3.065 35.766 3.721 ;
     RECT  2.415 3.721 35.766 3.725 ;
     RECT  5.04 3.725 35.766 3.811 ;
     RECT  36.756 3.415 40.662 3.811 ;
     RECT  5.04 3.811 40.662 3.883 ;
     RECT  5.04 3.883 41.13 3.991 ;
     RECT  5.04 3.991 41.202 4.081 ;
     RECT  5.04 4.081 41.49 4.109 ;
     RECT  5.04 4.109 23.202 4.145 ;
     RECT  23.94 4.109 41.49 4.225 ;
     RECT  23.94 4.225 41.562 4.379 ;
     RECT  2.415 3.725 4.266 4.531 ;
     RECT  5.04 4.145 23.13 4.531 ;
     RECT  44.136 4.747 44.154 4.939 ;
     RECT  44.136 4.939 44.262 4.987 ;
     RECT  2.415 4.531 23.13 5.071 ;
     RECT  23.94 4.379 41.166 5.071 ;
     RECT  2.415 5.071 41.166 5.305 ;
     RECT  2.415 5.305 41.202 5.707 ;
     RECT  2.34 5.707 41.202 6.151 ;
     RECT  2.34 6.151 41.238 6.269 ;
     RECT  2.415 6.269 41.238 6.349 ;
     RECT  2.415 6.349 41.526 6.925 ;
     RECT  44.064 4.987 44.262 6.961 ;
     RECT  2.415 6.925 41.634 7.051 ;
     RECT  2.415 7.051 41.742 7.231 ;
     RECT  43.416 6.961 44.262 7.465 ;
     RECT  43.344 7.465 44.262 9.113 ;
     RECT  43.344 9.113 44.226 9.725 ;
     RECT  2.376 7.231 41.814 10.319 ;
     RECT  43.344 9.725 44.19 10.445 ;
     RECT  2.415 10.319 41.814 10.589 ;
     RECT  43.344 10.445 43.506 10.733 ;
     RECT  43.344 10.733 43.47 11.245 ;
     RECT  42.804 11.245 43.47 11.501 ;
     RECT  42.804 11.501 43.434 11.515 ;
     RECT  42.768 11.515 43.434 11.981 ;
     RECT  2.415 10.589 41.742 12.217 ;
     RECT  2.415 12.217 41.922 12.331 ;
     RECT  2.34 12.331 41.922 12.361 ;
     RECT  42.768 11.981 43.362 12.361 ;
     RECT  2.34 12.361 43.362 12.461 ;
     RECT  2.34 12.461 41.922 12.479 ;
     RECT  2.34 12.479 41.886 12.893 ;
     RECT  42.732 12.461 43.362 12.941 ;
     RECT  43.344 12.941 43.362 13.091 ;
     RECT  2.34 12.893 41.31 13.289 ;
     RECT  2.34 13.289 32.49 13.829 ;
     RECT  33.228 13.289 41.31 13.945 ;
     RECT  33.228 13.945 41.67 14.099 ;
     RECT  2.415 13.829 32.49 14.107 ;
     RECT  33.228 14.099 41.058 14.107 ;
     RECT  2.415 14.107 41.058 14.279 ;
     RECT  2.415 14.279 41.022 14.369 ;
     RECT  41.796 14.791 41.814 15.053 ;
     RECT  2.415 14.369 37.797 15.061 ;
     RECT  0.54 14.989 0.558 15.259 ;
     RECT  38.7 14.369 41.022 15.259 ;
     RECT  0.504 15.259 0.558 15.437 ;
     RECT  2.304 15.061 37.797 15.457 ;
     RECT  38.7 15.259 41.094 15.457 ;
     RECT  0.504 15.437 0.522 15.533 ;
     RECT  2.304 15.457 41.094 15.871 ;
     RECT  44.244 15.565 44.262 16.411 ;
     RECT  2.304 15.871 41.274 16.537 ;
     RECT  0.54 16.339 0.558 16.589 ;
     RECT  44.208 16.411 44.262 16.681 ;
     RECT  2.304 16.537 41.562 17.041 ;
     RECT  0.144 16.891 0.162 17.069 ;
     RECT  2.304 17.041 41.598 17.185 ;
     RECT  2.304 17.185 41.994 17.339 ;
     RECT  0.216 17.323 0.342 17.453 ;
     RECT  0.216 17.453 0.234 17.549 ;
     RECT  2.304 17.339 41.886 18.059 ;
     RECT  2.376 18.059 41.886 18.185 ;
     RECT  2.376 18.185 41.814 18.419 ;
     RECT  2.376 18.419 41.526 18.689 ;
     RECT  44.172 16.681 44.262 18.805 ;
     RECT  44.1 18.805 44.262 18.914 ;
     RECT  44.1 18.914 44.226 18.959 ;
     RECT  43.02 15.493 43.038 19.111 ;
     RECT  44.1 18.959 44.19 19.111 ;
     RECT  2.415 18.689 41.526 19.273 ;
     RECT  2.415 19.273 41.922 19.769 ;
     RECT  43.02 19.111 44.19 19.813 ;
     RECT  42.804 19.813 44.19 19.885 ;
     RECT  2.415 19.769 41.886 20.011 ;
     RECT  42.768 19.885 44.19 20.155 ;
     RECT  42.732 20.155 44.19 20.237 ;
     RECT  2.376 20.011 41.886 20.389 ;
     RECT  0.108 19.921 0.126 20.717 ;
     RECT  0.144 20.779 0.162 21.001 ;
     RECT  2.304 20.389 41.886 21.355 ;
     RECT  42.768 20.237 44.19 21.355 ;
     RECT  0.144 21.001 0.558 21.389 ;
     RECT  0.504 21.389 0.558 21.469 ;
     RECT  2.304 21.355 44.19 21.485 ;
     RECT  0.504 21.469 1.17 21.505 ;
     RECT  0.504 21.505 1.242 21.659 ;
     RECT  2.304 21.485 44.154 21.677 ;
     RECT  2.304 21.677 43.614 21.731 ;
     RECT  2.304 21.731 41.922 22.199 ;
     RECT  0.504 21.659 0.558 22.267 ;
     RECT  42.768 21.731 43.614 22.555 ;
     RECT  2.304 22.199 41.886 22.637 ;
     RECT  2.376 22.637 41.886 22.781 ;
     RECT  42.768 22.555 43.686 22.811 ;
     RECT  0.144 22.267 0.558 22.843 ;
     RECT  0.144 22.843 0.594 22.919 ;
     RECT  0.144 22.919 0.558 23.405 ;
     RECT  43.344 22.811 43.686 23.405 ;
     RECT  43.38 23.405 43.686 23.597 ;
     RECT  43.452 23.597 43.686 23.693 ;
     RECT  2.415 22.781 41.886 23.701 ;
     RECT  2.304 23.701 41.886 23.891 ;
     RECT  44.172 23.899 44.262 23.963 ;
     RECT  44.172 23.963 44.19 23.981 ;
     RECT  0.144 23.405 0.162 24.413 ;
     RECT  2.34 23.891 41.886 24.431 ;
     RECT  1.152 24.331 1.17 24.461 ;
     RECT  2.34 24.431 4.014 24.461 ;
     RECT  2.34 24.461 3.942 24.467 ;
     RECT  2.415 24.467 3.942 24.503 ;
     RECT  4.824 24.431 41.886 25.169 ;
     RECT  2.415 24.503 3.438 25.321 ;
     RECT  4.824 25.169 16.578 25.321 ;
     RECT  17.46 25.169 41.886 25.475 ;
     RECT  17.784 25.475 41.886 25.511 ;
     RECT  2.415 25.321 16.578 26.095 ;
     RECT  2.376 26.095 16.578 26.221 ;
     RECT  2.376 26.221 17.046 26.293 ;
     RECT  17.856 25.511 41.886 26.293 ;
     RECT  43.344 25.861 43.362 26.429 ;
     RECT  44.244 26.491 44.262 26.527 ;
     RECT  44.172 26.527 44.262 26.825 ;
     RECT  44.172 26.825 44.19 26.861 ;
     RECT  2.376 26.293 41.886 27.059 ;
     RECT  43.416 27.373 43.434 27.481 ;
     RECT  23.688 27.059 41.886 27.595 ;
     RECT  43.38 27.481 43.434 27.691 ;
     RECT  23.688 27.595 42.21 27.715 ;
     RECT  43.344 27.691 43.434 27.715 ;
     RECT  23.688 27.715 43.434 27.841 ;
     RECT  23.436 27.841 43.434 27.905 ;
     RECT  0.108 27.913 0.126 28.021 ;
     RECT  36.828 27.905 43.434 28.109 ;
     RECT  23.436 27.905 36.09 28.183 ;
     RECT  36.828 28.109 43.362 28.211 ;
     RECT  2.415 27.059 22.662 28.267 ;
     RECT  36.828 28.211 42.21 28.283 ;
     RECT  2.304 28.267 22.662 28.319 ;
     RECT  0.108 28.021 0.522 28.453 ;
     RECT  2.415 28.319 22.662 28.489 ;
     RECT  23.4 28.183 36.09 28.489 ;
     RECT  0.108 28.453 0.558 28.589 ;
     RECT  43.344 28.211 43.362 28.685 ;
     RECT  36.828 28.283 41.886 29.255 ;
     RECT  0.108 28.589 0.522 29.261 ;
     RECT  0.468 29.261 0.522 29.323 ;
     RECT  2.415 28.489 36.09 29.335 ;
     RECT  36.828 29.255 41.634 29.335 ;
     RECT  2.415 29.335 41.634 29.405 ;
     RECT  0.468 29.323 0.594 29.453 ;
     RECT  2.415 29.405 36.09 29.707 ;
     RECT  37.116 29.405 41.634 30.181 ;
     RECT  2.304 29.707 36.09 30.221 ;
     RECT  0.108 29.995 0.198 30.254 ;
     RECT  0.144 30.254 0.198 30.283 ;
     RECT  0.144 30.283 0.342 30.413 ;
     RECT  2.376 30.221 36.09 30.415 ;
     RECT  37.116 30.181 41.742 30.415 ;
     RECT  0.144 30.413 0.306 30.509 ;
     RECT  2.376 30.415 41.742 30.991 ;
     RECT  0.216 30.509 0.306 31.133 ;
     RECT  0.216 31.133 0.234 31.229 ;
     RECT  2.34 30.991 41.742 31.243 ;
     RECT  2.268 31.243 41.742 31.451 ;
     RECT  2.415 31.451 41.742 31.649 ;
     RECT  2.415 31.649 41.634 31.919 ;
     RECT  2.415 31.919 41.31 32.611 ;
     RECT  2.376 32.611 41.31 32.729 ;
     RECT  33.192 32.729 41.31 32.845 ;
     RECT  2.376 32.729 32.397 33.053 ;
     RECT  33.192 32.845 41.562 33.115 ;
     RECT  2.415 33.053 32.397 33.541 ;
     RECT  33.192 33.115 41.994 33.541 ;
     RECT  2.415 33.541 41.994 33.581 ;
     RECT  33.192 33.581 41.994 34.079 ;
     RECT  2.415 33.581 32.397 34.465 ;
     RECT  33.192 34.079 41.562 34.465 ;
     RECT  2.415 34.465 41.562 35.005 ;
     RECT  2.415 35.005 41.994 35.131 ;
     RECT  2.376 35.131 41.994 35.159 ;
     RECT  2.376 35.159 41.562 35.429 ;
     RECT  2.415 35.429 41.562 36.121 ;
     RECT  2.415 36.121 41.67 37.705 ;
     RECT  2.376 37.705 41.67 38.173 ;
     RECT  2.376 38.173 41.814 38.399 ;
     RECT  2.376 38.399 41.67 38.435 ;
     RECT  2.376 38.435 41.31 38.705 ;
     RECT  2.415 38.705 41.31 38.741 ;
     RECT  2.415 38.741 41.238 40.441 ;
     RECT  2.415 40.441 41.67 40.873 ;
     RECT  2.34 40.873 41.67 40.973 ;
     RECT  2.34 40.973 30.114 41.171 ;
     RECT  30.852 40.973 41.67 41.251 ;
     RECT  30.852 41.251 41.994 41.369 ;
     RECT  2.415 41.171 30.114 41.405 ;
     RECT  30.852 41.369 41.31 41.513 ;
     RECT  2.415 41.405 26.997 41.549 ;
     RECT  31.896 41.513 41.31 41.549 ;
     RECT  36.504 41.549 41.31 41.597 ;
     RECT  2.415 41.549 10.998 41.639 ;
     RECT  32.004 41.549 35.73 41.639 ;
     RECT  12.024 41.549 26.997 41.675 ;
     RECT  36.576 41.597 41.31 41.675 ;
     RECT  3.924 41.639 10.998 41.693 ;
     RECT  27.792 41.405 30.114 41.719 ;
     RECT  30.852 41.513 31.158 41.719 ;
     RECT  3.924 41.693 6.174 41.783 ;
     RECT  12.024 41.675 14.454 41.783 ;
     RECT  15.552 41.675 25.938 41.783 ;
     RECT  32.115 41.639 35.73 41.783 ;
     RECT  36.648 41.675 41.31 41.783 ;
     RECT  15.552 41.783 18.897 41.867 ;
     RECT  26.715 41.675 26.997 41.867 ;
     RECT  32.115 41.783 35.097 41.867 ;
     RECT  2.415 41.639 3.078 41.885 ;
     RECT  4.104 41.783 6.174 41.909 ;
     RECT  6.912 41.693 9.378 41.909 ;
     RECT  10.152 41.693 10.998 41.909 ;
     RECT  13.068 41.783 14.454 41.909 ;
     RECT  19.836 41.783 25.722 41.909 ;
     RECT  27.792 41.719 31.158 41.909 ;
     RECT  36.648 41.783 39.33 41.909 ;
     RECT  9.36 41.909 9.378 41.933 ;
     RECT  13.068 41.909 13.95 41.933 ;
     RECT  4.608 41.909 5.742 41.945 ;
     RECT  6.912 41.909 8.262 41.945 ;
     RECT  12.024 41.783 12.15 41.945 ;
     RECT  15.552 41.867 18.705 41.945 ;
     RECT  19.836 41.909 22.446 41.945 ;
     RECT  23.724 41.909 24.354 41.945 ;
     RECT  25.2 41.909 25.218 41.945 ;
     RECT  27.792 41.909 27.81 41.945 ;
     RECT  28.62 41.909 30.33 41.945 ;
     RECT  31.14 41.909 31.158 41.945 ;
     RECT  32.115 41.867 34.905 41.945 ;
     RECT  36.648 41.909 36.666 41.945 ;
     RECT  38.376 41.909 39.33 41.945 ;
     RECT  40.14 41.783 41.31 41.945 ;
     RECT  6.984 41.945 7.905 41.981 ;
     RECT  12.132 41.945 12.15 41.981 ;
     RECT  17.64 41.945 17.658 41.981 ;
     RECT  18.432 41.945 18.705 41.981 ;
     RECT  21.06 41.945 21.834 41.981 ;
     RECT  28.728 41.945 29.505 41.981 ;
     RECT  15.552 41.945 16.254 42.017 ;
     RECT  40.14 41.945 41.166 42.017 ;
     RECT  13.215 41.933 13.95 42.053 ;
     RECT  18.54 41.981 18.705 42.053 ;
     RECT  4.608 41.945 5.205 42.089 ;
     RECT  6.984 41.981 7.002 42.089 ;
     RECT  10.515 41.909 10.674 42.089 ;
     RECT  21.06 41.981 21.405 42.089 ;
     RECT  23.832 41.945 24.354 42.089 ;
     RECT  30.312 41.945 30.33 42.089 ;
     RECT  39.024 41.945 39.042 42.089 ;
     RECT  40.14 42.017 40.914 42.089 ;
     RECT  2.415 41.885 2.505 42.137 ;
     RECT  5.115 42.089 5.205 42.137 ;
     RECT  7.815 41.981 7.905 42.137 ;
     RECT  10.515 42.089 10.605 42.137 ;
     RECT  13.215 42.053 13.305 42.137 ;
     RECT  15.915 42.017 16.005 42.137 ;
     RECT  18.615 42.053 18.705 42.137 ;
     RECT  21.315 42.089 21.405 42.137 ;
     RECT  23.832 42.089 24.105 42.137 ;
     RECT  26.715 41.867 26.805 42.137 ;
     RECT  29.415 41.981 29.505 42.137 ;
     RECT  32.115 41.945 32.205 42.137 ;
     RECT  33.012 41.945 34.905 42.137 ;
     RECT  37.515 41.909 37.605 42.137 ;
     RECT  40.215 42.089 40.305 42.137 ;
     RECT  23.832 42.137 23.85 42.179 ;
     RECT  33.012 42.137 34.11 42.797 ;
     RECT  33.3 42.797 34.11 43.277 ;
     RECT  33.3 43.277 33.966 43.325 ;
     RECT  33.3 43.325 33.642 43.421 ;
     RECT  33.3 43.421 33.462 44.045 ;
     RECT  33.444 44.045 33.462 44.189 ;
    LAYER M4 ;
     RECT  0.084 20.304 0.133 24.36 ;
     RECT  0.133 20.304 0.137 24.408 ;
     RECT  0.137 20.4 1.141 24.408 ;
     RECT  1.141 20.4 2.365 24.456 ;
     RECT  2.293 4.512 2.408 4.536 ;
     RECT  2.293 5.712 2.408 5.736 ;
     RECT  2.329 12.336 2.408 12.36 ;
     RECT  0.084 15.216 2.408 18.216 ;
     RECT  2.365 20.064 2.408 24.456 ;
     RECT  0.084 28.272 2.408 31.272 ;
     RECT  2.365 33.024 2.408 33.048 ;
     RECT  2.408 2.148 2.512 42.132 ;
     RECT  2.512 2.418 2.704 41.88 ;
     RECT  2.704 15.552 2.729 18.024 ;
     RECT  2.704 34.176 3.125 41.88 ;
     RECT  2.704 26.16 3.269 33.144 ;
     RECT  3.269 26.16 3.485 32.616 ;
     RECT  3.125 35.328 3.491 41.88 ;
     RECT  3.491 35.328 3.635 39.432 ;
     RECT  3.635 36.48 3.701 39.432 ;
     RECT  3.485 26.16 3.724 31.416 ;
     RECT  2.704 3.84 3.733 5.352 ;
     RECT  2.729 15.696 3.769 18.024 ;
     RECT  3.635 35.328 3.773 35.352 ;
     RECT  3.125 34.176 3.913 34.2 ;
     RECT  2.704 6.672 3.949 7.752 ;
     RECT  3.949 6.672 4.021 8.52 ;
     RECT  3.949 9.696 4.021 10.392 ;
     RECT  2.704 19.392 4.025 24.456 ;
     RECT  3.733 3.84 4.316 5.688 ;
     RECT  4.021 6.672 4.364 10.392 ;
     RECT  2.704 11.424 4.364 14.184 ;
     RECT  3.769 15.456 4.417 18.024 ;
     RECT  4.316 3.696 4.453 5.688 ;
     RECT  4.364 6.672 4.453 14.184 ;
     RECT  4.025 19.392 4.453 23.688 ;
     RECT  3.724 26.784 4.489 31.416 ;
     RECT  3.485 32.592 4.489 32.616 ;
     RECT  3.913 33.6 4.489 34.2 ;
     RECT  4.489 26.784 4.525 34.2 ;
     RECT  4.525 26.784 4.705 35.256 ;
     RECT  4.453 3.696 4.741 14.184 ;
     RECT  4.417 15.216 4.921 18.024 ;
     RECT  4.453 19.296 4.921 23.688 ;
     RECT  3.491 40.944 5.101 41.88 ;
     RECT  4.741 2.832 5.108 14.184 ;
     RECT  4.921 15.216 5.108 23.688 ;
     RECT  4.705 26.352 5.108 35.256 ;
     RECT  3.701 36.48 5.108 39.288 ;
     RECT  5.101 40.848 5.108 41.88 ;
     RECT  5.108 2.148 5.212 42.132 ;
     RECT  5.212 2.256 5.404 41.862 ;
     RECT  5.404 26.352 5.465 35.064 ;
     RECT  5.404 36.288 5.603 41.688 ;
     RECT  5.404 6.672 5.681 25.08 ;
     RECT  5.603 36.528 6.193 41.688 ;
     RECT  5.681 8.064 6.221 25.08 ;
     RECT  5.404 2.256 6.323 5.592 ;
     RECT  6.323 2.256 6.401 4.008 ;
     RECT  5.465 26.4 6.428 35.064 ;
     RECT  6.193 40.464 6.437 41.688 ;
     RECT  5.681 6.672 6.469 6.888 ;
     RECT  6.401 2.256 6.611 2.856 ;
     RECT  6.221 8.064 6.761 11.352 ;
     RECT  6.323 5.04 6.812 5.592 ;
     RECT  6.469 6.624 6.812 6.888 ;
     RECT  6.812 5.04 6.853 6.888 ;
     RECT  6.761 8.064 6.853 10.488 ;
     RECT  6.428 26.4 7.333 35.544 ;
     RECT  7.333 26.112 7.381 35.544 ;
     RECT  6.193 36.528 7.381 39.288 ;
     RECT  6.401 3.84 7.513 4.008 ;
     RECT  6.853 5.04 7.513 10.488 ;
     RECT  6.611 2.256 7.657 2.616 ;
     RECT  6.221 12.48 7.665 25.08 ;
     RECT  7.381 26.112 7.665 39.288 ;
     RECT  7.657 2.256 7.808 2.856 ;
     RECT  7.513 3.84 7.808 10.488 ;
     RECT  7.665 12.48 7.808 39.288 ;
     RECT  6.437 40.512 7.808 41.688 ;
     RECT  7.808 2.148 7.912 42.132 ;
     RECT  7.912 2.418 8.104 41.928 ;
     RECT  8.104 18.72 8.165 23.592 ;
     RECT  8.104 25.008 8.165 41.928 ;
     RECT  8.165 26.112 8.243 41.928 ;
     RECT  8.104 2.496 8.453 7.128 ;
     RECT  8.453 2.496 8.633 5.784 ;
     RECT  8.104 12.048 8.669 17.64 ;
     RECT  8.243 26.112 8.669 38.808 ;
     RECT  8.633 2.592 8.813 5.784 ;
     RECT  8.165 18.816 8.813 23.592 ;
     RECT  8.669 26.208 8.921 38.808 ;
     RECT  8.813 18.864 8.957 23.592 ;
     RECT  8.957 19.296 9.133 23.592 ;
     RECT  8.669 12.432 9.173 17.64 ;
     RECT  8.165 25.008 9.209 25.032 ;
     RECT  8.921 26.208 9.209 28.2 ;
     RECT  8.243 40.08 9.389 41.928 ;
     RECT  8.104 8.448 9.452 10.968 ;
     RECT  9.452 8.16 9.541 10.968 ;
     RECT  9.133 19.296 9.601 23.976 ;
     RECT  8.453 6.768 9.685 7.128 ;
     RECT  9.541 8.16 9.685 11.016 ;
     RECT  8.921 29.28 9.733 38.808 ;
     RECT  9.389 40.08 9.733 41.88 ;
     RECT  8.813 2.784 9.889 5.784 ;
     RECT  9.685 6.768 9.889 11.016 ;
     RECT  9.601 19.296 9.961 24.408 ;
     RECT  9.173 12.48 10.033 17.64 ;
     RECT  9.961 18.96 10.033 24.408 ;
     RECT  9.209 26.256 10.105 28.2 ;
     RECT  9.733 29.28 10.105 41.88 ;
     RECT  10.105 26.256 10.177 41.88 ;
     RECT  9.889 2.784 10.508 11.016 ;
     RECT  10.033 12.48 10.508 24.408 ;
     RECT  10.177 25.728 10.508 41.88 ;
     RECT  10.508 2.148 10.612 42.132 ;
     RECT  10.612 2.256 10.804 41.862 ;
     RECT  10.804 18.192 10.973 41.496 ;
     RECT  10.973 40.416 11.081 41.496 ;
     RECT  10.804 12.48 11.189 14.808 ;
     RECT  10.973 25.872 11.225 39.384 ;
     RECT  11.225 26.304 11.459 39.384 ;
     RECT  11.459 35.808 11.549 39.384 ;
     RECT  10.973 18.192 11.693 24.648 ;
     RECT  11.549 38.112 12.017 39.384 ;
     RECT  11.189 13.056 12.049 14.808 ;
     RECT  10.804 15.984 12.157 16.92 ;
     RECT  11.081 40.656 12.157 41.496 ;
     RECT  10.804 2.256 12.181 11.448 ;
     RECT  12.049 13.056 12.181 14.952 ;
     RECT  12.181 2.256 12.227 14.952 ;
     RECT  12.227 12.192 12.301 14.952 ;
     RECT  12.157 15.984 12.301 16.968 ;
     RECT  12.301 12.192 12.304 16.968 ;
     RECT  11.459 26.304 12.517 34.776 ;
     RECT  11.549 35.808 12.517 36.792 ;
     RECT  11.693 18.192 12.697 23.832 ;
     RECT  12.304 12.192 12.733 17.016 ;
     RECT  12.697 18.192 12.733 23.928 ;
     RECT  12.193 24.96 12.733 24.984 ;
     RECT  12.517 26.304 12.913 36.792 ;
     RECT  12.913 26.112 12.949 36.792 ;
     RECT  12.017 38.112 12.949 38.184 ;
     RECT  12.733 24.96 13.021 25.08 ;
     RECT  12.949 26.112 13.021 38.184 ;
     RECT  12.157 39.792 13.057 41.496 ;
     RECT  12.733 12.192 13.093 23.928 ;
     RECT  13.021 24.96 13.093 38.184 ;
     RECT  12.227 2.256 13.208 10.92 ;
     RECT  13.093 12.192 13.208 38.184 ;
     RECT  13.057 39.792 13.208 41.928 ;
     RECT  13.208 2.148 13.312 42.132 ;
     RECT  13.312 2.256 13.504 41.928 ;
     RECT  13.504 28.992 13.529 38.76 ;
     RECT  13.504 39.792 13.601 41.928 ;
     RECT  13.504 19.056 13.673 27.384 ;
     RECT  13.504 16.08 13.709 17.64 ;
     RECT  13.504 2.256 13.997 14.952 ;
     RECT  13.997 2.256 14.033 12.552 ;
     RECT  13.673 19.056 14.177 24.12 ;
     RECT  14.033 2.256 14.195 5.304 ;
     RECT  14.033 6.288 14.213 12.552 ;
     RECT  13.529 35.328 14.285 38.76 ;
     RECT  14.285 35.328 14.321 35.544 ;
     RECT  14.213 7.2 14.393 12.552 ;
     RECT  14.285 36.576 14.581 38.76 ;
     RECT  13.601 39.888 14.581 41.928 ;
     RECT  13.997 13.536 14.645 14.952 ;
     RECT  13.673 25.296 14.669 27.384 ;
     RECT  14.669 25.296 14.825 27.864 ;
     RECT  14.825 25.776 14.861 27.864 ;
     RECT  13.529 28.992 14.885 34.152 ;
     RECT  14.321 35.328 14.885 35.352 ;
     RECT  14.195 2.832 14.933 5.304 ;
     RECT  14.861 26.112 15.001 27.864 ;
     RECT  14.885 28.992 15.001 35.352 ;
     RECT  14.177 19.296 15.109 24.12 ;
     RECT  14.393 7.2 15.361 7.656 ;
     RECT  15.361 7.104 15.404 7.656 ;
     RECT  15.404 6.768 15.445 7.656 ;
     RECT  14.393 8.832 15.445 12.552 ;
     RECT  14.645 13.632 15.596 14.952 ;
     RECT  13.709 16.128 15.596 17.64 ;
     RECT  15.445 6.768 15.721 12.552 ;
     RECT  15.001 26.112 15.793 35.352 ;
     RECT  15.721 6.576 15.829 12.552 ;
     RECT  14.933 3.072 15.908 5.304 ;
     RECT  15.829 6.336 15.908 12.552 ;
     RECT  15.596 13.632 15.908 17.64 ;
     RECT  15.109 19.296 15.908 24.504 ;
     RECT  15.793 26.112 15.908 35.448 ;
     RECT  14.581 36.576 15.908 41.928 ;
     RECT  15.908 2.148 16.012 42.132 ;
     RECT  16.012 2.418 16.204 41.928 ;
     RECT  16.204 26.592 16.265 41.928 ;
     RECT  16.204 9.792 16.355 14.52 ;
     RECT  16.204 15.504 16.589 16.824 ;
     RECT  16.355 9.792 16.625 12.552 ;
     RECT  16.204 3.12 16.661 8.76 ;
     RECT  16.265 26.592 16.913 32.568 ;
     RECT  16.913 26.592 16.931 32.472 ;
     RECT  16.931 28.8 16.949 32.472 ;
     RECT  16.265 33.648 17.237 41.928 ;
     RECT  17.237 38.496 17.309 41.928 ;
     RECT  16.355 13.632 17.317 14.52 ;
     RECT  17.317 13.632 17.363 14.904 ;
     RECT  16.204 18.096 17.525 18.12 ;
     RECT  17.363 14.688 17.561 14.904 ;
     RECT  16.204 19.248 17.593 25.08 ;
     RECT  17.237 33.648 17.597 37.416 ;
     RECT  16.661 3.408 17.629 8.76 ;
     RECT  16.625 10.08 17.629 12.552 ;
     RECT  16.589 16.08 17.629 16.824 ;
     RECT  16.931 26.592 17.665 27.336 ;
     RECT  17.629 9.792 17.701 12.552 ;
     RECT  17.363 13.632 17.701 13.704 ;
     RECT  17.593 19.248 17.797 25.272 ;
     RECT  17.665 26.304 17.797 27.336 ;
     RECT  17.629 15.744 17.917 16.824 ;
     RECT  17.629 2.832 17.989 8.76 ;
     RECT  17.701 9.792 17.989 13.704 ;
     RECT  16.949 29.136 17.989 32.472 ;
     RECT  17.597 33.648 17.989 34.44 ;
     RECT  17.797 19.248 18.205 27.336 ;
     RECT  17.989 2.832 18.349 13.704 ;
     RECT  17.561 14.688 18.349 14.712 ;
     RECT  18.205 19.248 18.385 27.72 ;
     RECT  17.989 29.136 18.385 34.44 ;
     RECT  18.349 2.832 18.421 14.712 ;
     RECT  17.917 15.744 18.421 16.92 ;
     RECT  18.421 15.744 18.565 17.064 ;
     RECT  18.421 2.592 18.608 14.712 ;
     RECT  18.565 15.744 18.608 18.024 ;
     RECT  18.385 19.248 18.608 34.44 ;
     RECT  17.597 35.424 18.608 37.416 ;
     RECT  17.309 38.496 18.608 41.496 ;
     RECT  18.608 2.148 18.712 42.132 ;
     RECT  18.712 2.418 18.904 41.862 ;
     RECT  18.904 7.248 19.397 36.936 ;
     RECT  18.904 40.848 19.433 41.544 ;
     RECT  19.397 7.248 19.577 20.376 ;
     RECT  18.904 38.784 19.613 38.808 ;
     RECT  19.397 21.36 19.685 36.84 ;
     RECT  18.904 5.808 20.009 6.264 ;
     RECT  19.685 21.36 20.153 36.456 ;
     RECT  19.577 10.128 20.225 20.376 ;
     RECT  20.009 6.24 20.473 6.264 ;
     RECT  19.577 7.248 20.473 9.144 ;
     RECT  18.904 2.544 21.013 4.776 ;
     RECT  20.473 6.24 21.013 9.144 ;
     RECT  21.013 6.096 21.085 9.144 ;
     RECT  20.225 10.128 21.085 18.792 ;
     RECT  21.013 2.256 21.109 4.776 ;
     RECT  21.085 6.096 21.109 18.792 ;
     RECT  20.153 21.36 21.121 28.248 ;
     RECT  20.153 29.328 21.229 36.456 ;
     RECT  21.109 2.256 21.308 18.792 ;
     RECT  20.225 20.016 21.308 20.376 ;
     RECT  21.121 21.36 21.308 28.296 ;
     RECT  21.229 29.328 21.308 37.032 ;
     RECT  19.433 41.52 21.308 41.544 ;
     RECT  21.308 2.148 21.412 42.132 ;
     RECT  21.412 2.256 21.604 41.862 ;
     RECT  21.604 2.256 21.665 5.592 ;
     RECT  21.604 7.872 21.665 20.376 ;
     RECT  21.604 21.456 21.737 35.784 ;
     RECT  21.665 9.6 21.773 20.376 ;
     RECT  21.604 40.992 21.773 41.016 ;
     RECT  21.773 9.6 21.989 18.984 ;
     RECT  21.665 2.256 22.241 3.144 ;
     RECT  22.241 3.12 22.313 3.144 ;
     RECT  21.773 20.016 22.597 20.376 ;
     RECT  21.737 21.456 22.597 27.96 ;
     RECT  21.737 29.088 22.741 35.784 ;
     RECT  21.604 36.912 22.741 36.936 ;
     RECT  21.604 38.736 22.741 39.768 ;
     RECT  21.665 7.872 22.777 7.896 ;
     RECT  22.741 29.088 22.787 39.768 ;
     RECT  22.777 7.44 22.789 7.896 ;
     RECT  21.665 4.752 22.813 5.592 ;
     RECT  22.789 7.44 22.835 8.856 ;
     RECT  22.813 4.704 22.837 5.592 ;
     RECT  22.835 7.44 22.883 7.464 ;
     RECT  22.837 4.704 22.925 6.216 ;
     RECT  22.787 37.872 22.997 38.184 ;
     RECT  22.885 41.136 23.065 41.16 ;
     RECT  22.835 8.832 23.209 8.856 ;
     RECT  22.597 20.016 23.413 27.96 ;
     RECT  22.787 29.088 23.413 36.888 ;
     RECT  22.787 39.744 23.641 39.768 ;
     RECT  23.065 41.136 23.641 41.544 ;
     RECT  21.989 10.128 23.797 18.984 ;
     RECT  23.413 20.016 23.797 36.888 ;
     RECT  22.925 4.704 23.929 5.688 ;
     RECT  23.209 8.832 23.929 9.096 ;
     RECT  23.797 10.128 23.929 36.888 ;
     RECT  23.929 4.512 24.001 5.688 ;
     RECT  23.749 2.88 24.008 2.904 ;
     RECT  24.001 4.512 24.008 6.12 ;
     RECT  23.929 8.832 24.008 36.888 ;
     RECT  22.997 38.16 24.008 38.184 ;
     RECT  23.641 39.744 24.008 41.544 ;
     RECT  24.008 2.148 24.112 42.132 ;
     RECT  24.112 2.418 24.304 41.862 ;
     RECT  24.304 20.976 24.437 32.616 ;
     RECT  24.304 33.648 24.545 38.232 ;
     RECT  24.545 33.648 24.581 34.2 ;
     RECT  24.304 2.88 25.049 3.432 ;
     RECT  24.545 35.28 25.091 38.232 ;
     RECT  24.437 21.504 25.193 32.616 ;
     RECT  24.304 4.512 25.229 13.368 ;
     RECT  25.229 7.92 25.276 13.368 ;
     RECT  25.276 8.208 25.297 13.368 ;
     RECT  24.304 14.448 25.297 17.688 ;
     RECT  24.304 19.44 25.297 19.608 ;
     RECT  25.229 4.656 25.337 6.84 ;
     RECT  25.297 8.208 25.445 17.688 ;
     RECT  25.297 19.44 25.477 20.424 ;
     RECT  25.193 21.504 25.477 32.52 ;
     RECT  25.445 15.984 25.481 17.688 ;
     RECT  24.581 33.888 25.513 34.2 ;
     RECT  25.091 35.28 25.513 37.896 ;
     RECT  25.477 19.44 25.525 32.52 ;
     RECT  24.304 40.368 25.661 41.592 ;
     RECT  25.525 19.44 25.909 20.856 ;
     RECT  25.049 3.408 26.053 3.432 ;
     RECT  25.661 40.368 26.053 41.496 ;
     RECT  26.053 40.08 26.164 41.496 ;
     RECT  25.513 33.888 26.293 37.896 ;
     RECT  25.585 39.024 26.293 39.048 ;
     RECT  25.445 8.208 26.557 14.952 ;
     RECT  25.481 16.272 26.557 17.688 ;
     RECT  25.337 4.704 26.581 6.84 ;
     RECT  26.557 8.208 26.581 17.688 ;
     RECT  26.293 33.888 26.581 39.048 ;
     RECT  26.164 40.032 26.581 41.496 ;
     RECT  26.053 3.408 26.708 3.672 ;
     RECT  26.581 4.704 26.708 17.688 ;
     RECT  25.909 18.72 26.708 20.856 ;
     RECT  25.525 21.936 26.708 32.52 ;
     RECT  26.581 33.888 26.708 41.496 ;
     RECT  26.708 2.148 26.812 42.132 ;
     RECT  26.812 2.418 27.004 41.862 ;
     RECT  27.004 21.648 27.155 37.416 ;
     RECT  27.004 38.688 27.317 41.64 ;
     RECT  27.155 21.648 27.461 36.984 ;
     RECT  27.317 40.944 27.461 41.64 ;
     RECT  27.317 38.688 27.497 39.24 ;
     RECT  27.004 2.832 27.641 17.16 ;
     RECT  27.461 21.648 27.677 36.6 ;
     RECT  27.641 6.384 27.713 16.968 ;
     RECT  27.713 6.384 27.857 11.544 ;
     RECT  27.713 12.528 27.893 16.968 ;
     RECT  27.677 24.912 27.965 36.6 ;
     RECT  27.497 38.688 27.965 38.712 ;
     RECT  27.965 24.912 28.073 36.024 ;
     RECT  27.677 21.648 28.141 23.928 ;
     RECT  27.004 18.816 28.357 18.84 ;
     RECT  28.141 21.6 28.393 23.928 ;
     RECT  28.508 37.296 28.753 37.32 ;
     RECT  28.357 18.816 28.825 19.032 ;
     RECT  27.857 7.344 29.041 11.544 ;
     RECT  27.893 12.528 29.041 16.92 ;
     RECT  29.041 7.344 29.077 16.92 ;
     RECT  28.073 33.216 29.077 36.024 ;
     RECT  28.753 37.296 29.077 37.608 ;
     RECT  27.004 20.064 29.113 20.136 ;
     RECT  28.393 21.408 29.113 23.928 ;
     RECT  28.825 18.24 29.173 19.032 ;
     RECT  29.113 20.064 29.173 23.928 ;
     RECT  28.753 40.416 29.173 40.44 ;
     RECT  27.641 2.832 29.365 5.16 ;
     RECT  29.365 2.256 29.408 5.16 ;
     RECT  29.077 7.344 29.408 17.16 ;
     RECT  29.173 18.24 29.408 23.928 ;
     RECT  28.073 24.912 29.408 32.232 ;
     RECT  29.077 33.216 29.408 37.608 ;
     RECT  29.173 39.6 29.408 40.44 ;
     RECT  27.461 41.616 29.408 41.64 ;
     RECT  29.408 2.148 29.512 42.132 ;
     RECT  29.512 2.256 29.704 41.862 ;
     RECT  29.704 15.84 29.729 16.008 ;
     RECT  29.704 3.648 29.843 5.16 ;
     RECT  29.704 6.672 29.909 14.76 ;
     RECT  29.704 17.088 29.945 17.112 ;
     RECT  29.909 7.824 29.981 14.76 ;
     RECT  29.981 7.92 30.413 14.76 ;
     RECT  29.704 34.704 30.521 35.544 ;
     RECT  30.521 34.704 30.593 35.448 ;
     RECT  30.413 14.4 30.769 14.76 ;
     RECT  29.729 15.984 30.769 16.008 ;
     RECT  29.704 40.416 30.769 40.44 ;
     RECT  30.769 14.4 30.805 16.008 ;
     RECT  29.704 38.688 30.805 38.712 ;
     RECT  29.704 19.776 30.809 19.8 ;
     RECT  30.593 34.704 30.845 35.352 ;
     RECT  30.805 38.688 30.877 38.856 ;
     RECT  29.909 6.672 30.881 6.84 ;
     RECT  30.413 7.92 30.881 13.368 ;
     RECT  30.881 6.672 30.913 6.696 ;
     RECT  29.704 31.104 30.913 31.128 ;
     RECT  29.704 32.208 30.913 32.232 ;
     RECT  29.704 2.256 30.989 2.28 ;
     RECT  30.769 40.368 31.021 40.44 ;
     RECT  29.704 20.88 31.025 24.648 ;
     RECT  29.843 4.32 31.045 5.16 ;
     RECT  30.805 14.4 31.061 16.584 ;
     RECT  31.045 3.936 31.132 5.16 ;
     RECT  31.132 4.608 31.165 5.16 ;
     RECT  30.913 6.336 31.165 6.696 ;
     RECT  29.704 25.632 31.165 30.024 ;
     RECT  30.913 31.104 31.165 32.232 ;
     RECT  29.704 33.504 31.273 33.528 ;
     RECT  30.881 8.208 31.417 13.368 ;
     RECT  31.061 14.4 31.417 16.008 ;
     RECT  31.021 40.368 31.436 41.064 ;
     RECT  31.025 20.928 31.489 24.648 ;
     RECT  31.165 25.632 31.489 32.232 ;
     RECT  30.845 34.704 31.921 34.92 ;
     RECT  31.453 18.816 31.993 18.84 ;
     RECT  31.813 2.88 32.108 2.904 ;
     RECT  31.165 4.608 32.108 6.696 ;
     RECT  31.417 8.208 32.108 16.008 ;
     RECT  31.993 18.72 32.108 18.84 ;
     RECT  31.201 19.92 32.108 19.944 ;
     RECT  31.489 20.928 32.108 32.232 ;
     RECT  31.273 33.504 32.108 33.624 ;
     RECT  31.921 34.704 32.108 35.256 ;
     RECT  29.704 36.528 32.108 36.552 ;
     RECT  30.877 38.688 32.108 38.904 ;
     RECT  31.436 39.984 32.108 41.064 ;
     RECT  32.108 2.148 32.212 42.132 ;
     RECT  32.212 2.256 32.404 42.132 ;
     RECT  32.404 4.656 32.573 6.072 ;
     RECT  32.404 17.472 32.681 19.416 ;
     RECT  32.404 20.88 32.753 29.064 ;
     RECT  32.753 21.504 32.933 29.064 ;
     RECT  32.404 7.104 32.969 16.008 ;
     RECT  32.404 30.192 33.041 32.232 ;
     RECT  33.041 30.432 33.113 32.232 ;
     RECT  32.404 40.32 33.113 41.64 ;
     RECT  33.061 43.92 33.245 43.944 ;
     RECT  33.245 43.92 33.328 44.04 ;
     RECT  32.681 18.048 33.365 19.416 ;
     RECT  33.328 43.92 33.433 44.088 ;
     RECT  32.969 7.296 33.481 16.008 ;
     RECT  33.001 42.768 33.493 42.792 ;
     RECT  33.433 43.92 33.493 44.184 ;
     RECT  33.493 42.768 33.517 44.184 ;
     RECT  33.517 42.768 33.539 44.088 ;
     RECT  33.539 42.768 33.587 43.416 ;
     RECT  32.404 33.552 33.613 33.576 ;
     RECT  32.404 34.752 33.613 35.448 ;
     RECT  32.933 21.984 33.635 29.064 ;
     RECT  33.613 33.552 33.637 35.448 ;
     RECT  32.404 36.48 33.637 37.032 ;
     RECT  33.113 41.616 33.637 41.64 ;
     RECT  33.637 33.552 33.653 37.032 ;
     RECT  32.573 4.656 33.685 5.736 ;
     RECT  33.637 41.616 33.733 41.688 ;
     RECT  33.653 34.176 33.757 37.032 ;
     RECT  33.113 30.96 33.865 32.232 ;
     RECT  33.587 43.248 33.875 43.416 ;
     RECT  33.901 20.928 33.973 20.952 ;
     RECT  33.635 21.984 33.973 23.928 ;
     RECT  33.875 43.248 33.977 43.32 ;
     RECT  33.635 24.912 34.076 29.064 ;
     RECT  33.685 4.656 34.081 6.264 ;
     RECT  34.076 24.912 34.117 29.976 ;
     RECT  33.865 30.96 34.117 33.096 ;
     RECT  33.977 43.248 34.121 43.272 ;
     RECT  32.404 38.4 34.172 39.288 ;
     RECT  33.113 40.32 34.172 40.584 ;
     RECT  34.172 38.4 34.213 40.584 ;
     RECT  33.733 41.616 34.213 41.832 ;
     RECT  33.365 18.24 34.513 19.416 ;
     RECT  33.973 20.928 34.513 23.928 ;
     RECT  32.404 2.256 34.808 3.432 ;
     RECT  34.081 4.56 34.808 6.264 ;
     RECT  33.481 7.296 34.808 15.576 ;
     RECT  34.513 18.24 34.808 23.928 ;
     RECT  34.117 24.912 34.808 33.096 ;
     RECT  33.757 34.176 34.808 37.08 ;
     RECT  34.213 38.4 34.808 41.832 ;
     RECT  34.808 2.148 34.912 42.132 ;
     RECT  34.912 2.256 35.104 41.862 ;
     RECT  35.104 34.368 35.219 37.128 ;
     RECT  35.104 38.4 35.417 39 ;
     RECT  35.104 30.72 35.425 33.096 ;
     RECT  35.104 7.392 35.507 16.68 ;
     RECT  35.104 2.256 35.633 2.28 ;
     RECT  35.507 12.864 35.705 16.68 ;
     RECT  35.417 38.4 35.777 38.76 ;
     RECT  35.425 31.248 35.891 33.096 ;
     RECT  35.219 34.512 35.939 37.128 ;
     RECT  35.939 35.904 35.957 37.128 ;
     RECT  35.891 31.92 36.029 32.856 ;
     RECT  35.507 7.392 36.245 11.784 ;
     RECT  35.104 40.704 36.313 40.728 ;
     RECT  35.705 12.864 36.353 16.536 ;
     RECT  36.353 12.864 36.389 16.44 ;
     RECT  35.104 17.952 36.425 29.4 ;
     RECT  35.104 4.56 36.493 5.928 ;
     RECT  36.245 7.392 36.493 8.52 ;
     RECT  36.313 40.464 36.493 40.728 ;
     RECT  36.389 13.104 36.497 16.44 ;
     RECT  35.939 34.512 36.497 34.728 ;
     RECT  35.957 35.904 36.497 35.928 ;
     RECT  36.493 40.464 36.601 41.592 ;
     RECT  36.493 4.56 36.637 8.52 ;
     RECT  35.957 37.056 36.709 37.128 ;
     RECT  35.777 38.4 36.709 38.664 ;
     RECT  36.709 37.056 36.812 38.664 ;
     RECT  36.029 32.016 36.925 32.856 ;
     RECT  36.812 37.056 36.925 38.952 ;
     RECT  36.601 39.984 36.925 41.592 ;
     RECT  36.925 32.016 37.105 33.048 ;
     RECT  37.105 31.92 37.213 33.048 ;
     RECT  36.745 30.576 37.249 30.6 ;
     RECT  37.213 31.68 37.249 33.048 ;
     RECT  36.497 13.344 37.381 16.44 ;
     RECT  36.425 17.952 37.381 19.56 ;
     RECT  37.045 2.256 37.508 2.28 ;
     RECT  36.637 3.84 37.508 8.52 ;
     RECT  36.245 9.504 37.508 11.784 ;
     RECT  37.381 13.344 37.508 19.56 ;
     RECT  36.425 20.688 37.508 29.4 ;
     RECT  37.249 30.576 37.508 33.048 ;
     RECT  36.497 34.656 37.508 34.728 ;
     RECT  36.925 37.056 37.508 41.592 ;
     RECT  37.508 2.148 37.612 42.132 ;
     RECT  37.612 2.418 37.804 41.862 ;
     RECT  37.804 18.816 37.865 32.856 ;
     RECT  37.804 2.832 37.937 17.64 ;
     RECT  37.937 3.84 37.973 17.64 ;
     RECT  37.937 2.832 38.189 2.856 ;
     RECT  37.973 3.84 38.189 15.384 ;
     RECT  38.189 4.272 38.195 15.384 ;
     RECT  38.195 9.504 38.261 14.952 ;
     RECT  38.195 4.272 38.297 7.992 ;
     RECT  37.804 34.176 38.297 34.2 ;
     RECT  37.804 38.16 38.297 40.536 ;
     RECT  37.804 35.808 38.621 35.832 ;
     RECT  38.297 4.272 38.801 6.84 ;
     RECT  37.865 18.816 38.801 29.736 ;
     RECT  38.297 38.16 38.833 39.192 ;
     RECT  38.801 26.064 38.905 29.736 ;
     RECT  37.865 30.768 38.905 30.792 ;
     RECT  38.869 35.088 39.053 35.112 ;
     RECT  38.261 9.504 39.265 13.08 ;
     RECT  38.801 4.272 39.301 6.36 ;
     RECT  39.265 9.072 39.301 13.08 ;
     RECT  38.261 14.496 39.301 14.952 ;
     RECT  37.973 16.368 39.301 17.64 ;
     RECT  38.801 18.816 39.301 25.08 ;
     RECT  38.297 7.968 39.337 7.992 ;
     RECT  39.301 9.072 39.337 14.952 ;
     RECT  38.833 37.536 39.345 39.192 ;
     RECT  38.297 40.464 39.345 40.536 ;
     RECT  39.337 7.968 39.445 14.952 ;
     RECT  39.301 16.368 39.445 25.08 ;
     RECT  37.865 31.968 39.445 32.856 ;
     RECT  38.905 26.064 39.517 30.792 ;
     RECT  39.445 31.968 39.517 33.048 ;
     RECT  39.445 7.968 39.553 25.08 ;
     RECT  39.301 36.288 39.697 36.312 ;
     RECT  39.697 35.856 39.781 36.312 ;
     RECT  39.345 37.536 39.781 40.536 ;
     RECT  39.301 4.224 39.805 6.36 ;
     RECT  39.553 7.344 39.805 25.08 ;
     RECT  39.805 4.224 39.841 25.08 ;
     RECT  39.517 26.064 39.841 33.048 ;
     RECT  39.781 35.856 39.877 40.536 ;
     RECT  39.541 3.168 40.208 3.192 ;
     RECT  39.841 4.224 40.208 33.048 ;
     RECT  39.877 35.856 40.208 41.208 ;
     RECT  40.208 2.148 40.312 42.132 ;
     RECT  40.312 2.418 40.504 41.862 ;
     RECT  40.504 31.152 40.529 31.992 ;
     RECT  40.504 26.064 40.565 30.12 ;
     RECT  40.504 36.288 40.565 36.552 ;
     RECT  40.504 38.688 40.565 39.336 ;
     RECT  40.504 13.632 40.601 14.52 ;
     RECT  40.504 8.448 40.637 12.312 ;
     RECT  40.504 19.536 40.643 25.08 ;
     RECT  40.565 30.096 40.643 30.12 ;
     RECT  40.504 15.84 40.673 18.264 ;
     RECT  40.504 41.136 40.709 41.352 ;
     RECT  40.601 13.632 40.817 13.704 ;
     RECT  40.673 16.656 40.817 18.264 ;
     RECT  40.504 37.584 40.817 37.608 ;
     RECT  40.504 6.336 40.889 7.416 ;
     RECT  40.643 19.632 40.925 25.08 ;
     RECT  40.817 17.136 40.931 18.264 ;
     RECT  40.931 17.184 40.933 18.264 ;
     RECT  40.933 17.184 40.961 17.544 ;
     RECT  40.925 25.056 40.969 25.08 ;
     RECT  40.637 8.448 40.997 11.4 ;
     RECT  40.565 36.288 40.997 36.312 ;
     RECT  40.997 9.072 41.033 11.4 ;
     RECT  40.504 4.224 41.069 5.016 ;
     RECT  40.889 6.672 41.069 7.416 ;
     RECT  41.033 9.072 41.069 9.096 ;
     RECT  40.817 13.68 41.069 13.704 ;
     RECT  40.961 17.52 41.069 17.544 ;
     RECT  40.504 33.024 41.069 33.528 ;
     RECT  40.529 31.152 41.105 31.944 ;
     RECT  40.565 39.216 41.105 39.336 ;
     RECT  41.105 39.312 41.141 39.336 ;
     RECT  41.069 7.392 41.213 7.416 ;
     RECT  41.069 33.504 41.321 33.528 ;
     RECT  40.925 19.632 41.393 23.928 ;
     RECT  40.709 41.328 41.429 41.352 ;
     RECT  41.033 10.128 41.641 11.4 ;
     RECT  41.641 10.128 41.857 11.784 ;
     RECT  41.857 10.128 42.721 12.744 ;
     RECT  41.393 20.304 42.721 23.928 ;
     RECT  42.721 20.208 42.757 23.928 ;
     RECT  42.721 10.128 44.053 12.936 ;
     RECT  44.053 10.032 44.089 12.936 ;
     RECT  41.069 4.752 44.093 5.016 ;
     RECT  42.757 19.92 44.161 23.928 ;
     RECT  44.093 4.752 44.165 4.968 ;
     RECT  44.089 9.696 44.22 9.864 ;
     RECT  44.089 9.864 44.196 12.936 ;
     RECT  44.161 19.92 44.196 23.976 ;
     RECT  40.565 26.064 44.196 29.064 ;
     RECT  44.22 9.696 44.237 9.72 ;
     RECT  44.165 4.944 44.273 4.968 ;
    LAYER M5 ;
     RECT  2.4 2.137 2.52 2.151 ;
     RECT  5.1 2.137 5.22 2.151 ;
     RECT  7.8 2.137 7.92 2.151 ;
     RECT  10.5 2.137 10.62 2.151 ;
     RECT  13.2 2.137 13.32 2.151 ;
     RECT  15.9 2.137 16.02 2.151 ;
     RECT  18.6 2.137 18.72 2.151 ;
     RECT  21.3 2.137 21.42 2.151 ;
     RECT  24 2.137 24.12 2.151 ;
     RECT  26.7 2.137 26.82 2.151 ;
     RECT  29.4 2.137 29.52 2.151 ;
     RECT  32.1 2.137 32.22 2.151 ;
     RECT  34.8 2.137 34.92 2.151 ;
     RECT  37.5 2.137 37.62 2.151 ;
     RECT  40.2 2.137 40.32 2.151 ;
     RECT  5.1 2.151 5.412 2.245 ;
     RECT  13.2 2.151 13.512 2.245 ;
     RECT  37.5 2.151 37.812 2.245 ;
     RECT  5.1 2.245 6.312 2.581 ;
     RECT  7.8 2.151 8.112 2.677 ;
     RECT  10.5 2.151 10.812 2.773 ;
     RECT  18.6 2.151 18.912 2.821 ;
     RECT  26.7 2.151 27.012 3.157 ;
     RECT  40.2 2.151 40.512 3.157 ;
     RECT  10.5 2.773 11.016 3.397 ;
     RECT  34.8 2.151 35.112 3.397 ;
     RECT  17.856 2.821 18.912 3.445 ;
     RECT  7.8 2.677 8.52 3.635 ;
     RECT  10.5 3.397 11.928 3.635 ;
     RECT  29.4 2.151 29.712 3.637 ;
     RECT  5.1 2.581 6.6 3.685 ;
     RECT  37.056 2.245 37.812 3.875 ;
     RECT  26.7 3.157 27.912 3.925 ;
     RECT  29.4 3.637 29.832 3.925 ;
     RECT  26.7 3.925 29.832 3.971 ;
     RECT  39.552 3.157 40.512 4.259 ;
     RECT  31.056 3.925 31.08 4.355 ;
     RECT  2.4 2.151 2.712 4.501 ;
     RECT  33.984 3.397 35.112 4.549 ;
     RECT  28.464 3.971 29.832 4.597 ;
     RECT  32.1 2.151 32.412 4.645 ;
     RECT  28.464 4.597 30.792 4.739 ;
     RECT  4.368 3.685 6.6 4.979 ;
     RECT  15.9 2.151 16.212 5.077 ;
     RECT  17.616 3.445 18.912 5.077 ;
     RECT  4.56 4.979 6.6 5.123 ;
     RECT  15.9 5.077 18.912 5.171 ;
     RECT  28.464 4.739 29.928 5.171 ;
     RECT  33.984 4.549 35.784 5.171 ;
     RECT  7.8 3.635 8.28 5.173 ;
     RECT  17.856 5.171 18.912 5.219 ;
     RECT  6.576 5.123 6.6 5.267 ;
     RECT  15.9 5.171 16.824 5.269 ;
     RECT  21.3 2.151 21.612 5.557 ;
     RECT  10.5 3.635 11.304 5.605 ;
     RECT  24 2.151 24.312 5.605 ;
     RECT  22.944 5.125 22.968 5.699 ;
     RECT  2.304 4.501 2.712 5.747 ;
     RECT  33.984 5.171 35.112 5.747 ;
     RECT  24 5.605 24.456 6.085 ;
     RECT  26.7 3.971 27.012 6.085 ;
     RECT  10.272 5.605 11.304 6.131 ;
     RECT  7.8 5.173 8.52 6.133 ;
     RECT  18.6 5.219 18.912 6.229 ;
     RECT  37.5 3.875 37.812 6.229 ;
     RECT  37.5 6.229 38.184 6.373 ;
     RECT  21.12 5.557 21.612 6.613 ;
     RECT  13.2 2.245 14.184 6.661 ;
     RECT  4.56 5.123 5.412 6.805 ;
     RECT  6.864 6.133 8.52 6.805 ;
     RECT  10.5 6.131 11.304 7.043 ;
     RECT  12.96 6.661 14.184 7.189 ;
     RECT  12.288 7.189 14.184 7.381 ;
     RECT  4.56 6.805 8.52 7.475 ;
     RECT  22.848 6.181 22.872 7.475 ;
     RECT  18.096 6.229 18.912 7.573 ;
     RECT  4.56 7.475 6.072 7.621 ;
     RECT  9.504 7.093 9.528 7.621 ;
     RECT  10.5 7.043 10.812 7.621 ;
     RECT  29.4 5.171 29.928 7.859 ;
     RECT  24 6.085 24.504 7.909 ;
     RECT  12.288 7.381 14.328 7.957 ;
     RECT  11.952 7.957 14.328 8.003 ;
     RECT  33.696 6.229 33.72 8.149 ;
     RECT  34.8 5.747 35.112 8.149 ;
     RECT  9.504 7.621 10.812 8.195 ;
     RECT  15.456 5.269 16.824 8.195 ;
     RECT  33.696 8.149 35.112 8.195 ;
     RECT  30.816 7.909 30.84 8.197 ;
     RECT  31.968 4.645 32.412 8.197 ;
     RECT  4.416 7.621 6.072 8.437 ;
     RECT  24 7.909 25.224 8.437 ;
     RECT  26.592 6.085 27.012 8.437 ;
     RECT  7.8 7.475 8.52 8.483 ;
     RECT  11.952 8.003 13.656 8.483 ;
     RECT  37.392 6.373 38.184 8.531 ;
     RECT  24 8.437 27.012 8.579 ;
     RECT  33.936 8.195 35.112 8.723 ;
     RECT  4.416 8.437 6.264 8.725 ;
     RECT  7.8 8.483 8.112 8.725 ;
     RECT  20.544 6.613 21.612 8.771 ;
     RECT  22.8 7.861 22.824 8.867 ;
     RECT  24 8.579 25.224 8.963 ;
     RECT  40.08 4.259 40.512 9.061 ;
     RECT  30.816 8.197 32.412 9.107 ;
     RECT  4.416 8.725 8.112 9.251 ;
     RECT  26.592 8.579 27.012 9.253 ;
     RECT  34.8 8.723 35.112 9.349 ;
     RECT  36.144 9.061 36.168 9.349 ;
     RECT  11.952 8.483 13.512 9.539 ;
     RECT  26.592 9.253 27.144 9.589 ;
     RECT  17.904 7.573 18.912 9.637 ;
     RECT  34.8 9.349 36.168 9.685 ;
     RECT  11.952 9.539 12.216 9.731 ;
     RECT  15.9 8.195 16.824 9.781 ;
     RECT  34.704 9.685 36.168 9.827 ;
     RECT  4.416 9.251 6.264 9.923 ;
     RECT  39.36 9.061 40.512 9.923 ;
     RECT  15.264 9.781 16.824 10.069 ;
     RECT  17.904 9.637 19.368 10.069 ;
     RECT  37.5 8.531 38.184 10.165 ;
     RECT  15.264 10.069 19.368 10.307 ;
     RECT  24 8.963 24.456 10.355 ;
     RECT  4.416 9.923 6.072 10.595 ;
     RECT  36.864 10.165 38.184 10.789 ;
     RECT  15.264 10.307 18.912 10.883 ;
     RECT  31.056 9.107 32.412 10.931 ;
     RECT  31.056 10.931 31.08 10.979 ;
     RECT  39.792 9.923 40.512 10.979 ;
     RECT  40.08 10.979 40.512 10.981 ;
     RECT  9.552 8.195 10.812 11.027 ;
     RECT  20.736 8.771 21.612 11.027 ;
     RECT  24 10.355 24.408 11.077 ;
     RECT  29.4 7.859 29.832 11.125 ;
     RECT  29.088 11.125 29.832 11.267 ;
     RECT  40.08 10.981 40.632 11.315 ;
     RECT  15.264 10.883 16.824 11.411 ;
     RECT  2.4 5.747 2.712 11.413 ;
     RECT  36.432 10.789 38.184 11.459 ;
     RECT  40.08 11.315 40.512 11.459 ;
     RECT  36.432 11.459 36.456 11.651 ;
     RECT  18.6 10.883 18.912 11.845 ;
     RECT  2.4 11.413 3.144 12.035 ;
     RECT  33.6 10.501 33.624 12.179 ;
     RECT  12.192 9.731 12.216 12.227 ;
     RECT  5.1 10.595 6.072 12.325 ;
     RECT  34.8 9.827 35.352 12.325 ;
     RECT  4.128 12.325 6.072 12.467 ;
     RECT  10.5 11.027 10.812 12.469 ;
     RECT  15.648 11.411 16.824 12.517 ;
     RECT  23.472 11.077 24.408 12.517 ;
     RECT  40.2 11.459 40.512 12.517 ;
     RECT  29.136 11.267 29.832 13.045 ;
     RECT  10.176 12.469 10.812 13.091 ;
     RECT  29.04 13.045 29.832 13.141 ;
     RECT  23.184 12.517 24.408 13.283 ;
     RECT  18.6 11.845 19.512 13.331 ;
     RECT  28.896 13.141 29.832 13.379 ;
     RECT  32.1 10.931 32.412 13.621 ;
     RECT  33.408 13.333 33.432 13.621 ;
     RECT  14.832 12.517 17.352 13.715 ;
     RECT  4.128 12.467 5.412 13.811 ;
     RECT  28.896 13.379 29.712 13.811 ;
     RECT  39.36 12.517 40.512 13.811 ;
     RECT  26.016 9.589 27.144 13.907 ;
     RECT  18.6 13.331 19.368 14.147 ;
     RECT  34.8 12.325 35.496 14.149 ;
     RECT  34.8 14.149 35.64 14.245 ;
     RECT  26.016 13.907 27.012 14.291 ;
     RECT  23.184 13.283 24.312 14.533 ;
     RECT  7.8 9.251 8.112 14.677 ;
     RECT  15.648 13.715 17.352 14.915 ;
     RECT  26.592 14.291 27.012 14.917 ;
     RECT  26.592 14.917 27.144 15.013 ;
     RECT  26.592 15.013 27.48 15.155 ;
     RECT  29.088 13.811 29.712 15.301 ;
     RECT  34.8 14.245 35.976 15.301 ;
     RECT  37.5 11.459 38.184 15.301 ;
     RECT  32.1 13.621 33.432 15.347 ;
     RECT  34.8 15.301 38.184 15.395 ;
     RECT  13.2 9.539 13.512 15.445 ;
     RECT  7.584 14.677 8.112 15.491 ;
     RECT  33.408 15.347 33.432 15.541 ;
     RECT  0.144 15.541 0.168 15.827 ;
     RECT  26.592 15.155 27.336 15.923 ;
     RECT  26.592 15.923 27.144 16.019 ;
     RECT  28.512 15.301 29.712 16.019 ;
     RECT  33.408 15.541 33.624 16.019 ;
     RECT  36.72 15.395 38.04 16.019 ;
     RECT  15.648 14.915 16.392 16.357 ;
     RECT  12.528 15.445 13.512 16.451 ;
     RECT  5.1 13.811 5.412 16.501 ;
     RECT  30.816 15.349 30.84 16.595 ;
     RECT  40.2 13.811 40.512 16.645 ;
     RECT  15.648 16.357 16.536 16.789 ;
     RECT  7.68 15.491 8.112 16.885 ;
     RECT  7.68 16.885 9.096 17.123 ;
     RECT  12.96 16.451 13.512 17.123 ;
     RECT  40.2 16.645 40.632 17.125 ;
     RECT  29.088 16.019 29.712 17.171 ;
     RECT  0.144 17.173 0.168 17.459 ;
     RECT  32.1 15.347 32.412 17.461 ;
     RECT  23.136 14.533 24.312 17.651 ;
     RECT  37.392 16.019 38.04 17.699 ;
     RECT  34.8 15.395 35.112 17.989 ;
     RECT  40.2 17.125 40.92 18.275 ;
     RECT  13.2 17.123 13.512 18.565 ;
     RECT  25.488 16.885 25.512 18.709 ;
     RECT  26.592 16.019 27.012 18.709 ;
     RECT  10.5 13.091 10.812 18.805 ;
     RECT  40.2 18.275 40.632 18.853 ;
     RECT  37.5 17.699 38.04 18.997 ;
     RECT  34.8 17.989 35.544 19.235 ;
     RECT  7.68 17.123 8.76 19.237 ;
     RECT  18.6 14.147 18.912 19.237 ;
     RECT  5.1 16.501 5.832 19.333 ;
     RECT  32.1 17.461 32.52 19.427 ;
     RECT  15.648 16.789 16.92 19.525 ;
     RECT  7.68 19.237 8.808 19.571 ;
     RECT  7.8 19.571 8.808 19.715 ;
     RECT  37.5 18.997 38.184 19.957 ;
     RECT  39.312 18.853 40.632 19.957 ;
     RECT  12.528 18.565 13.512 20.003 ;
     RECT  20.064 17.653 20.088 20.003 ;
     RECT  25.488 18.709 27.012 20.003 ;
     RECT  37.5 19.957 40.632 20.003 ;
     RECT  18.6 19.237 19.08 20.149 ;
     RECT  12.96 20.003 13.512 20.339 ;
     RECT  21.12 11.027 21.612 20.341 ;
     RECT  23.328 17.651 24.312 20.341 ;
     RECT  5.1 19.333 6.168 20.579 ;
     RECT  15.072 19.525 16.92 20.579 ;
     RECT  18.192 20.149 19.08 20.629 ;
     RECT  40.08 20.003 40.632 20.675 ;
     RECT  10.272 18.805 10.812 20.723 ;
     RECT  29.136 17.171 29.712 20.869 ;
     RECT  18.192 20.629 19.224 20.963 ;
     RECT  37.5 20.003 38.76 21.059 ;
     RECT  15.648 20.579 16.344 21.155 ;
     RECT  22.752 20.341 24.312 21.155 ;
     RECT  18.192 20.963 19.128 21.299 ;
     RECT  20.352 20.341 21.612 21.395 ;
     RECT  33.6 16.019 33.624 21.397 ;
     RECT  34.8 19.235 35.112 21.397 ;
     RECT  32.1 19.427 32.412 21.493 ;
     RECT  33.6 21.397 35.112 21.493 ;
     RECT  25.488 20.003 25.512 21.683 ;
     RECT  29.136 20.869 30.216 21.683 ;
     RECT  29.136 21.683 29.712 21.733 ;
     RECT  2.4 12.035 2.712 21.781 ;
     RECT  26.7 20.003 27.012 21.829 ;
     RECT  28.416 21.733 29.712 21.829 ;
     RECT  26.7 21.829 29.712 21.875 ;
     RECT  18.192 21.299 19.032 21.925 ;
     RECT  10.5 20.723 10.812 22.117 ;
     RECT  2.304 21.781 2.712 22.163 ;
     RECT  15.648 21.155 16.212 22.163 ;
     RECT  21.12 21.395 21.612 22.165 ;
     RECT  17.904 21.925 19.032 22.211 ;
     RECT  32.1 21.493 35.112 22.307 ;
     RECT  17.904 22.211 18.912 22.357 ;
     RECT  24 21.155 24.312 22.597 ;
     RECT  5.1 20.579 5.832 22.645 ;
     RECT  37.5 21.059 38.136 22.739 ;
     RECT  37.5 22.739 37.992 22.741 ;
     RECT  13.104 20.339 13.512 22.787 ;
     RECT  40.08 20.675 40.512 23.029 ;
     RECT  24 22.597 25.176 23.317 ;
     RECT  37.056 22.741 37.992 23.411 ;
     RECT  7.8 19.715 8.112 23.557 ;
     RECT  39.984 23.029 40.512 23.653 ;
     RECT  37.296 23.411 37.992 23.699 ;
     RECT  13.2 22.787 13.512 23.797 ;
     RECT  26.7 21.875 27.48 23.845 ;
     RECT  28.512 21.875 29.712 23.845 ;
     RECT  22.752 21.155 22.776 23.891 ;
     RECT  26.7 23.845 29.712 23.891 ;
     RECT  17.808 22.357 18.912 23.941 ;
     RECT  10.5 22.117 10.92 23.987 ;
     RECT  7.536 23.557 8.112 24.131 ;
     RECT  15.9 22.163 16.212 24.277 ;
     RECT  21.12 22.165 21.72 24.469 ;
     RECT  17.808 23.941 19.032 24.709 ;
     RECT  26.7 23.891 27.624 24.901 ;
     RECT  29.136 23.891 29.712 24.901 ;
     RECT  39.984 23.653 40.872 24.901 ;
     RECT  15.792 24.277 16.212 25.045 ;
     RECT  17.808 24.709 19.752 25.045 ;
     RECT  24 23.317 25.224 25.045 ;
     RECT  32.1 22.307 33.624 25.045 ;
     RECT  39.888 24.901 40.872 25.045 ;
     RECT  13.104 23.797 13.512 25.091 ;
     RECT  21.12 24.469 22.68 25.091 ;
     RECT  26.7 24.901 29.712 25.235 ;
     RECT  15.792 25.045 19.752 25.475 ;
     RECT  21.12 25.091 21.612 25.525 ;
     RECT  17.904 25.475 19.752 25.571 ;
     RECT  13.2 25.091 13.512 25.621 ;
     RECT  24 25.045 25.464 25.715 ;
     RECT  31.872 25.045 33.624 25.763 ;
     RECT  37.296 23.699 37.812 25.765 ;
     RECT  28.512 25.235 29.712 25.955 ;
     RECT  7.68 24.131 8.112 26.101 ;
     RECT  37.296 25.765 38.76 26.147 ;
     RECT  2.4 22.163 2.712 26.149 ;
     RECT  21.024 25.525 21.612 26.243 ;
     RECT  22.656 25.091 22.68 26.387 ;
     RECT  26.7 25.235 27.012 26.389 ;
     RECT  29.232 25.955 29.712 26.435 ;
     RECT  10.5 23.987 10.812 26.485 ;
     RECT  13.2 25.621 14.28 26.485 ;
     RECT  12.96 26.485 14.28 26.581 ;
     RECT  12.96 26.581 14.712 26.627 ;
     RECT  14.688 26.627 14.712 26.629 ;
     RECT  15.792 25.475 16.872 26.629 ;
     RECT  14.688 26.629 16.872 26.771 ;
     RECT  39.888 25.045 40.92 26.771 ;
     RECT  2.4 26.149 3.672 26.819 ;
     RECT  7.44 26.101 8.112 26.819 ;
     RECT  31.872 25.763 33.528 26.915 ;
     RECT  26.304 26.389 27.012 26.965 ;
     RECT  30.768 25.765 30.792 27.011 ;
     RECT  5.1 22.645 5.976 27.205 ;
     RECT  39.984 26.771 40.92 27.299 ;
     RECT  37.296 26.147 37.812 27.395 ;
     RECT  32.1 26.915 33.528 27.779 ;
     RECT  24 25.715 25.128 27.827 ;
     RECT  14.688 26.771 14.712 27.875 ;
     RECT  7.8 26.819 8.112 27.877 ;
     RECT  15.792 26.771 16.872 27.877 ;
     RECT  37.392 27.395 37.812 27.877 ;
     RECT  5.1 27.205 6.312 27.923 ;
     RECT  24 27.827 24.936 28.213 ;
     RECT  29.4 26.435 29.712 28.309 ;
     RECT  26.208 26.965 27.012 28.453 ;
     RECT  34.8 22.307 35.112 28.453 ;
     RECT  17.904 25.571 18.912 28.501 ;
     RECT  12.96 26.627 13.608 28.547 ;
     RECT  37.392 27.877 38.232 28.547 ;
     RECT  15.792 27.877 16.92 28.835 ;
     RECT  10.368 26.485 10.812 28.885 ;
     RECT  26.208 28.453 27.912 29.123 ;
     RECT  3.984 28.405 4.008 29.219 ;
     RECT  29.088 28.309 29.712 29.267 ;
     RECT  34.8 28.453 35.88 29.411 ;
     RECT  21.12 26.243 21.612 29.509 ;
     RECT  15.792 28.835 16.488 29.605 ;
     RECT  20.976 29.509 21.612 29.605 ;
     RECT  15.408 29.605 16.488 29.747 ;
     RECT  32.1 27.779 33.432 29.941 ;
     RECT  34.8 29.411 35.4 29.941 ;
     RECT  30.816 28.453 30.84 30.035 ;
     RECT  17.904 28.501 19.608 30.181 ;
     RECT  20.832 29.605 21.612 30.229 ;
     RECT  23.424 28.213 24.936 30.229 ;
     RECT  5.1 27.923 5.976 30.275 ;
     RECT  26.304 29.123 27.912 30.371 ;
     RECT  10.32 28.885 10.812 30.419 ;
     RECT  7.8 27.877 8.52 30.611 ;
     RECT  0.144 30.373 0.168 30.659 ;
     RECT  20.832 30.229 24.936 30.659 ;
     RECT  5.1 30.275 5.412 30.709 ;
     RECT  10.368 30.419 10.812 30.803 ;
     RECT  32.1 29.941 35.4 30.803 ;
     RECT  23.472 30.659 24.936 30.851 ;
     RECT  17.904 30.181 19.752 30.899 ;
     RECT  13.104 28.547 13.608 31.043 ;
     RECT  15.408 29.747 16.44 31.043 ;
     RECT  24 30.851 24.936 31.139 ;
     RECT  39.984 27.299 40.632 31.139 ;
     RECT  40.2 31.139 40.632 31.187 ;
     RECT  13.2 31.043 13.608 31.237 ;
     RECT  34.8 30.803 35.4 31.237 ;
     RECT  4.752 30.709 5.412 31.379 ;
     RECT  18.6 30.899 19.752 31.379 ;
     RECT  20.832 30.659 22.488 31.379 ;
     RECT  26.7 30.371 27.912 31.861 ;
     RECT  29.4 29.267 29.712 31.861 ;
     RECT  37.392 28.547 37.812 31.955 ;
     RECT  15.9 31.043 16.44 32.005 ;
     RECT  13.2 31.237 13.848 32.197 ;
     RECT  15.312 32.005 16.584 32.243 ;
     RECT  32.1 30.803 33.432 32.243 ;
     RECT  18.6 31.379 18.912 32.389 ;
     RECT  15.648 32.243 16.584 32.437 ;
     RECT  13.104 32.197 13.848 32.483 ;
     RECT  26.7 31.861 29.712 32.531 ;
     RECT  13.2 32.483 13.848 32.723 ;
     RECT  24 31.139 24.456 32.917 ;
     RECT  2.4 26.819 2.712 33.013 ;
     RECT  20.832 31.379 21.612 33.059 ;
     RECT  34.8 31.237 35.88 33.107 ;
     RECT  27.984 32.531 29.712 33.251 ;
     RECT  18.192 32.389 18.912 33.541 ;
     RECT  18.192 33.541 19.032 33.587 ;
     RECT  7.8 30.611 8.376 33.589 ;
     RECT  31.008 31.093 31.032 33.589 ;
     RECT  32.1 32.243 33.336 33.589 ;
     RECT  5.1 31.379 5.412 33.637 ;
     RECT  13.2 32.723 13.656 33.683 ;
     RECT  15.648 32.437 17.064 33.779 ;
     RECT  26.7 32.531 27.012 33.877 ;
     RECT  27.984 33.251 28.056 33.877 ;
     RECT  15.648 33.779 16.872 33.925 ;
     RECT  26.7 33.877 28.056 34.165 ;
     RECT  12 34.117 12.024 34.259 ;
     RECT  26.208 34.165 28.056 34.357 ;
     RECT  29.088 33.251 29.712 34.357 ;
     RECT  34.8 33.107 35.112 34.357 ;
     RECT  7.68 33.589 8.568 34.643 ;
     RECT  10.5 30.803 10.812 34.693 ;
     RECT  31.008 33.589 33.336 34.741 ;
     RECT  14.928 33.925 16.872 34.835 ;
     RECT  31.008 34.741 33.672 34.883 ;
     RECT  7.68 34.643 8.112 35.221 ;
     RECT  13.2 33.683 13.608 35.269 ;
     RECT  18.6 33.587 19.032 35.269 ;
     RECT  26.208 34.357 29.712 35.269 ;
     RECT  34.8 34.357 35.208 35.269 ;
     RECT  12.96 35.269 13.608 35.317 ;
     RECT  5.1 33.637 5.544 35.509 ;
     RECT  7.344 35.221 8.112 35.509 ;
     RECT  9.936 34.693 10.812 35.509 ;
     RECT  25.728 35.269 29.712 35.699 ;
     RECT  2.4 33.013 2.808 35.797 ;
     RECT  2.4 35.797 2.856 35.845 ;
     RECT  3.936 33.589 3.96 35.845 ;
     RECT  34.8 35.269 35.928 35.939 ;
     RECT  25.728 35.699 27.528 36.035 ;
     RECT  23.232 32.917 24.456 36.421 ;
     RECT  25.728 36.035 27.192 36.421 ;
     RECT  23.232 36.421 27.192 36.469 ;
     RECT  9.936 35.509 11.448 36.515 ;
     RECT  22.752 36.469 27.192 36.515 ;
     RECT  31.2 34.883 33.672 36.515 ;
     RECT  24 36.515 27.192 36.563 ;
     RECT  12.96 35.317 14.232 36.611 ;
     RECT  18.6 35.269 19.416 36.613 ;
     RECT  15.648 34.835 16.212 36.659 ;
     RECT  2.4 35.845 3.96 36.851 ;
     RECT  18.48 36.613 19.416 36.851 ;
     RECT  15.9 36.659 16.212 36.901 ;
     RECT  34.8 35.939 35.256 36.995 ;
     RECT  38.88 29.605 38.904 36.997 ;
     RECT  40.2 31.187 40.512 36.997 ;
     RECT  9.12 36.853 9.144 37.043 ;
     RECT  28.56 35.699 29.712 37.331 ;
     RECT  10.32 36.515 11.448 37.379 ;
     RECT  12.96 36.611 13.608 37.379 ;
     RECT  24 36.563 27.144 37.427 ;
     RECT  10.32 37.379 10.812 37.573 ;
     RECT  37.5 31.955 37.812 37.573 ;
     RECT  15.9 36.901 16.344 37.621 ;
     RECT  12.96 37.379 13.512 37.667 ;
     RECT  13.104 37.667 13.512 37.715 ;
     RECT  24 37.427 27.012 37.907 ;
     RECT  2.4 36.851 2.904 37.957 ;
     RECT  3.936 36.851 3.96 37.957 ;
     RECT  2.4 37.957 3.96 38.003 ;
     RECT  22.752 36.515 22.776 38.149 ;
     RECT  24 37.907 25.08 38.149 ;
     RECT  36.864 37.573 37.812 38.197 ;
     RECT  38.88 36.997 40.512 38.197 ;
     RECT  22.752 38.149 25.08 38.243 ;
     RECT  36.864 38.197 40.512 38.243 ;
     RECT  39.792 38.243 40.512 38.387 ;
     RECT  36.864 38.243 38.76 38.435 ;
     RECT  9.84 37.573 10.812 38.677 ;
     RECT  14.832 38.197 14.856 38.771 ;
     RECT  5.1 35.509 8.112 38.773 ;
     RECT  22.752 38.243 24.312 38.915 ;
     RECT  26.064 37.907 27.012 39.013 ;
     RECT  15.9 37.621 17.16 39.253 ;
     RECT  18.48 36.851 18.912 39.253 ;
     RECT  31.2 36.515 33.336 39.253 ;
     RECT  5.1 38.773 8.232 39.539 ;
     RECT  29.4 37.331 29.712 39.589 ;
     RECT  36.864 38.435 38.664 39.733 ;
     RECT  39.84 38.387 40.512 39.733 ;
     RECT  9.744 38.677 10.812 39.779 ;
     RECT  13.2 37.715 13.512 39.877 ;
     RECT  14.592 39.253 14.712 39.877 ;
     RECT  31.2 39.253 33.432 39.877 ;
     RECT  34.8 36.995 35.112 39.877 ;
     RECT  13.2 39.877 14.712 39.923 ;
     RECT  15.9 39.253 18.912 39.923 ;
     RECT  36.864 39.733 40.512 40.019 ;
     RECT  26.064 39.013 27.144 40.115 ;
     RECT  2.4 38.003 3.864 40.355 ;
     RECT  23.712 38.915 24.312 40.355 ;
     RECT  29.184 39.589 29.712 40.451 ;
     RECT  5.1 39.539 8.112 40.499 ;
     RECT  18.48 39.923 18.912 40.499 ;
     RECT  31.2 39.877 35.112 40.499 ;
     RECT  37.5 40.019 40.512 40.499 ;
     RECT  39.36 40.499 40.512 40.547 ;
     RECT  6.72 40.499 8.112 40.595 ;
     RECT  6.816 40.595 8.112 40.837 ;
     RECT  14.688 39.923 14.712 40.883 ;
     RECT  15.9 39.923 17.208 40.883 ;
     RECT  3.84 40.355 3.864 40.933 ;
     RECT  26.7 40.115 27.144 40.979 ;
     RECT  3.84 40.933 3.96 41.075 ;
     RECT  17.184 40.883 17.208 41.075 ;
     RECT  23.904 40.355 24.312 41.075 ;
     RECT  32.1 40.499 35.112 41.075 ;
     RECT  13.2 39.923 13.704 41.411 ;
     RECT  6.816 40.837 8.376 41.651 ;
     RECT  3.936 41.075 3.96 41.891 ;
     RECT  10.176 39.779 10.812 41.891 ;
     RECT  7.8 41.651 8.376 41.939 ;
     RECT  2.4 40.355 2.712 42.129 ;
     RECT  5.1 40.499 5.412 42.129 ;
     RECT  7.8 41.939 8.112 42.129 ;
     RECT  10.5 41.891 10.812 42.129 ;
     RECT  13.2 41.411 13.512 42.129 ;
     RECT  15.9 40.883 16.212 42.129 ;
     RECT  18.6 40.499 18.912 42.129 ;
     RECT  21.3 33.059 21.612 42.129 ;
     RECT  24 41.075 24.312 42.129 ;
     RECT  26.7 40.979 27.012 42.129 ;
     RECT  29.4 40.451 29.712 42.129 ;
     RECT  34.8 41.075 35.112 42.129 ;
     RECT  37.5 40.499 37.812 42.129 ;
     RECT  40.2 40.547 40.512 42.129 ;
     RECT  2.4 42.129 2.52 42.143 ;
     RECT  5.1 42.129 5.22 42.143 ;
     RECT  7.8 42.129 7.92 42.143 ;
     RECT  10.5 42.129 10.62 42.143 ;
     RECT  13.2 42.129 13.32 42.143 ;
     RECT  15.9 42.129 16.02 42.143 ;
     RECT  18.6 42.129 18.72 42.143 ;
     RECT  21.3 42.129 21.42 42.143 ;
     RECT  24 42.129 24.12 42.143 ;
     RECT  26.7 42.129 26.82 42.143 ;
     RECT  29.4 42.129 29.52 42.143 ;
     RECT  32.1 41.075 33.768 42.143 ;
     RECT  34.8 42.129 34.92 42.143 ;
     RECT  37.5 42.129 37.62 42.143 ;
     RECT  40.2 42.129 40.32 42.143 ;
     RECT  33.168 42.143 33.768 43.237 ;
     RECT  33.168 43.237 34.056 43.909 ;
     RECT  33.072 43.909 34.056 44.196 ;
    LAYER M4 ;
      RECT  0.06 15.216 0.084 15.24 ;
      RECT  0.06 15.312 0.084 15.336 ;
      RECT  0.06 15.408 0.084 15.432 ;
      RECT  0.06 15.504 0.084 15.528 ;
      RECT  0.06 15.6 0.084 15.624 ;
      RECT  0.06 15.696 0.084 15.72 ;
      RECT  0.06 15.792 0.084 15.816 ;
      RECT  0.06 15.888 0.084 15.912 ;
      RECT  0.06 15.984 0.084 16.008 ;
      RECT  0.06 16.08 0.084 16.104 ;
      RECT  0.06 16.176 0.084 16.2 ;
      RECT  0.06 16.272 0.084 16.296 ;
      RECT  0.06 16.368 0.084 16.392 ;
      RECT  0.06 16.464 0.084 16.488 ;
      RECT  0.06 16.56 0.084 16.584 ;
      RECT  0.06 16.656 0.084 16.68 ;
      RECT  0.06 16.752 0.084 16.776 ;
      RECT  0.06 16.848 0.084 16.872 ;
      RECT  0.06 16.944 0.084 16.968 ;
      RECT  0.06 17.04 0.084 17.064 ;
      RECT  0.06 17.136 0.084 17.16 ;
      RECT  0.06 17.232 0.084 17.256 ;
      RECT  0.06 17.328 0.084 17.352 ;
      RECT  0.06 17.424 0.084 17.448 ;
      RECT  0.06 17.52 0.084 17.544 ;
      RECT  0.06 17.616 0.084 17.64 ;
      RECT  0.06 17.712 0.084 17.736 ;
      RECT  0.06 17.808 0.084 17.832 ;
      RECT  0.06 17.904 0.084 17.928 ;
      RECT  0.06 18 0.084 18.024 ;
      RECT  0.06 18.096 0.084 18.12 ;
      RECT  0.06 18.192 0.084 18.216 ;
      RECT  0.06 20.304 0.084 20.328 ;
      RECT  0.06 20.4 0.084 20.424 ;
      RECT  0.06 20.496 0.084 20.52 ;
      RECT  0.06 20.592 0.084 20.616 ;
      RECT  0.06 20.688 0.084 20.712 ;
      RECT  0.06 20.784 0.084 20.808 ;
      RECT  0.06 20.88 0.084 20.904 ;
      RECT  0.06 20.976 0.084 21 ;
      RECT  0.06 21.072 0.084 21.096 ;
      RECT  0.06 21.168 0.084 21.192 ;
      RECT  0.06 21.264 0.084 21.288 ;
      RECT  0.06 21.36 0.084 21.384 ;
      RECT  0.06 21.456 0.084 21.48 ;
      RECT  0.06 21.552 0.084 21.576 ;
      RECT  0.06 21.648 0.084 21.672 ;
      RECT  0.06 21.744 0.084 21.768 ;
      RECT  0.06 21.84 0.084 21.864 ;
      RECT  0.06 21.936 0.084 21.96 ;
      RECT  0.06 22.032 0.084 22.056 ;
      RECT  0.06 22.128 0.084 22.152 ;
      RECT  0.06 22.224 0.084 22.248 ;
      RECT  0.06 22.32 0.084 22.344 ;
      RECT  0.06 22.416 0.084 22.44 ;
      RECT  0.06 22.512 0.084 22.536 ;
      RECT  0.06 22.608 0.084 22.632 ;
      RECT  0.06 22.704 0.084 22.728 ;
      RECT  0.06 22.8 0.084 22.824 ;
      RECT  0.06 22.896 0.084 22.92 ;
      RECT  0.06 22.992 0.084 23.016 ;
      RECT  0.06 23.088 0.084 23.112 ;
      RECT  0.06 23.184 0.084 23.208 ;
      RECT  0.06 23.28 0.084 23.304 ;
      RECT  0.06 23.376 0.084 23.4 ;
      RECT  0.06 23.472 0.084 23.496 ;
      RECT  0.06 23.568 0.084 23.592 ;
      RECT  0.06 23.664 0.084 23.688 ;
      RECT  0.06 23.76 0.084 23.784 ;
      RECT  0.06 23.856 0.084 23.88 ;
      RECT  0.06 23.952 0.084 23.976 ;
      RECT  0.06 24.048 0.084 24.072 ;
      RECT  0.06 24.144 0.084 24.168 ;
      RECT  0.06 24.24 0.084 24.264 ;
      RECT  0.06 24.336 0.084 24.36 ;
      RECT  0.06 28.272 0.084 28.296 ;
      RECT  0.06 28.368 0.084 28.392 ;
      RECT  0.06 28.464 0.084 28.488 ;
      RECT  0.06 28.56 0.084 28.584 ;
      RECT  0.06 28.656 0.084 28.68 ;
      RECT  0.06 28.752 0.084 28.776 ;
      RECT  0.06 28.848 0.084 28.872 ;
      RECT  0.06 28.944 0.084 28.968 ;
      RECT  0.06 29.04 0.084 29.064 ;
      RECT  0.06 29.136 0.084 29.16 ;
      RECT  0.06 29.232 0.084 29.256 ;
      RECT  0.06 29.328 0.084 29.352 ;
      RECT  0.06 29.424 0.084 29.448 ;
      RECT  0.06 29.52 0.084 29.544 ;
      RECT  0.06 29.616 0.084 29.64 ;
      RECT  0.06 29.712 0.084 29.736 ;
      RECT  0.06 29.808 0.084 29.832 ;
      RECT  0.06 29.904 0.084 29.928 ;
      RECT  0.06 30 0.084 30.024 ;
      RECT  0.06 30.096 0.084 30.12 ;
      RECT  0.06 30.192 0.084 30.216 ;
      RECT  0.06 30.288 0.084 30.312 ;
      RECT  0.06 30.384 0.084 30.408 ;
      RECT  0.06 30.48 0.084 30.504 ;
      RECT  0.06 30.576 0.084 30.6 ;
      RECT  0.06 30.672 0.084 30.696 ;
      RECT  0.06 30.768 0.084 30.792 ;
      RECT  0.06 30.864 0.084 30.888 ;
      RECT  0.06 30.96 0.084 30.984 ;
      RECT  0.06 31.056 0.084 31.08 ;
      RECT  0.06 31.152 0.084 31.176 ;
      RECT  0.06 31.248 0.084 31.272 ;
      RECT  44.196 9.936 44.22 9.96 ;
      RECT  44.196 10.032 44.22 10.056 ;
      RECT  44.196 10.128 44.22 10.152 ;
      RECT  44.196 10.224 44.22 10.248 ;
      RECT  44.196 10.32 44.22 10.344 ;
      RECT  44.196 10.416 44.22 10.44 ;
      RECT  44.196 10.512 44.22 10.536 ;
      RECT  44.196 10.608 44.22 10.632 ;
      RECT  44.196 10.704 44.22 10.728 ;
      RECT  44.196 10.8 44.22 10.824 ;
      RECT  44.196 10.896 44.22 10.92 ;
      RECT  44.196 10.992 44.22 11.016 ;
      RECT  44.196 11.088 44.22 11.112 ;
      RECT  44.196 11.184 44.22 11.208 ;
      RECT  44.196 11.28 44.22 11.304 ;
      RECT  44.196 11.376 44.22 11.4 ;
      RECT  44.196 11.472 44.22 11.496 ;
      RECT  44.196 11.568 44.22 11.592 ;
      RECT  44.196 11.664 44.22 11.688 ;
      RECT  44.196 11.76 44.22 11.784 ;
      RECT  44.196 11.856 44.22 11.88 ;
      RECT  44.196 11.952 44.22 11.976 ;
      RECT  44.196 12.048 44.22 12.072 ;
      RECT  44.196 12.144 44.22 12.168 ;
      RECT  44.196 12.24 44.22 12.264 ;
      RECT  44.196 12.336 44.22 12.36 ;
      RECT  44.196 12.432 44.22 12.456 ;
      RECT  44.196 12.528 44.22 12.552 ;
      RECT  44.196 12.624 44.22 12.648 ;
      RECT  44.196 12.72 44.22 12.744 ;
      RECT  44.196 12.816 44.22 12.84 ;
      RECT  44.196 12.912 44.22 12.936 ;
      RECT  44.196 19.92 44.22 19.944 ;
      RECT  44.196 20.016 44.22 20.04 ;
      RECT  44.196 20.112 44.22 20.136 ;
      RECT  44.196 20.208 44.22 20.232 ;
      RECT  44.196 20.304 44.22 20.328 ;
      RECT  44.196 20.4 44.22 20.424 ;
      RECT  44.196 20.496 44.22 20.52 ;
      RECT  44.196 20.592 44.22 20.616 ;
      RECT  44.196 20.688 44.22 20.712 ;
      RECT  44.196 20.784 44.22 20.808 ;
      RECT  44.196 20.88 44.22 20.904 ;
      RECT  44.196 20.976 44.22 21 ;
      RECT  44.196 21.072 44.22 21.096 ;
      RECT  44.196 21.168 44.22 21.192 ;
      RECT  44.196 21.264 44.22 21.288 ;
      RECT  44.196 21.36 44.22 21.384 ;
      RECT  44.196 21.456 44.22 21.48 ;
      RECT  44.196 21.552 44.22 21.576 ;
      RECT  44.196 21.648 44.22 21.672 ;
      RECT  44.196 21.744 44.22 21.768 ;
      RECT  44.196 21.84 44.22 21.864 ;
      RECT  44.196 21.936 44.22 21.96 ;
      RECT  44.196 22.032 44.22 22.056 ;
      RECT  44.196 22.128 44.22 22.152 ;
      RECT  44.196 22.224 44.22 22.248 ;
      RECT  44.196 22.32 44.22 22.344 ;
      RECT  44.196 22.416 44.22 22.44 ;
      RECT  44.196 22.512 44.22 22.536 ;
      RECT  44.196 22.608 44.22 22.632 ;
      RECT  44.196 22.704 44.22 22.728 ;
      RECT  44.196 22.8 44.22 22.824 ;
      RECT  44.196 22.896 44.22 22.92 ;
      RECT  44.196 22.992 44.22 23.016 ;
      RECT  44.196 23.088 44.22 23.112 ;
      RECT  44.196 23.184 44.22 23.208 ;
      RECT  44.196 23.28 44.22 23.304 ;
      RECT  44.196 23.376 44.22 23.4 ;
      RECT  44.196 23.472 44.22 23.496 ;
      RECT  44.196 23.568 44.22 23.592 ;
      RECT  44.196 23.664 44.22 23.688 ;
      RECT  44.196 23.76 44.22 23.784 ;
      RECT  44.196 23.856 44.22 23.88 ;
      RECT  44.196 23.904 44.273 23.928 ;
      RECT  44.196 23.952 44.22 23.976 ;
      RECT  44.196 26.064 44.22 26.088 ;
      RECT  44.196 26.16 44.22 26.184 ;
      RECT  44.196 26.256 44.22 26.28 ;
      RECT  44.196 26.352 44.22 26.376 ;
      RECT  44.196 26.448 44.22 26.472 ;
      RECT  44.196 26.496 44.273 26.52 ;
      RECT  44.196 26.544 44.22 26.568 ;
      RECT  44.196 26.64 44.22 26.664 ;
      RECT  44.196 26.736 44.22 26.76 ;
      RECT  44.196 26.784 44.273 26.808 ;
      RECT  44.196 26.832 44.22 26.856 ;
      RECT  44.196 26.928 44.22 26.952 ;
      RECT  44.196 27.024 44.22 27.048 ;
      RECT  44.196 27.12 44.22 27.144 ;
      RECT  44.196 27.216 44.22 27.24 ;
      RECT  44.196 27.312 44.22 27.336 ;
      RECT  44.196 27.408 44.22 27.432 ;
      RECT  44.196 27.504 44.22 27.528 ;
      RECT  44.196 27.6 44.22 27.624 ;
      RECT  44.196 27.696 44.22 27.72 ;
      RECT  44.196 27.792 44.22 27.816 ;
      RECT  44.196 27.888 44.22 27.912 ;
      RECT  44.196 27.984 44.22 28.008 ;
      RECT  44.196 28.08 44.22 28.104 ;
      RECT  44.196 28.176 44.22 28.2 ;
      RECT  44.196 28.272 44.22 28.296 ;
      RECT  44.196 28.368 44.22 28.392 ;
      RECT  44.196 28.464 44.22 28.488 ;
      RECT  44.196 28.56 44.22 28.584 ;
      RECT  44.196 28.656 44.22 28.68 ;
      RECT  44.196 28.752 44.22 28.776 ;
      RECT  44.196 28.848 44.22 28.872 ;
      RECT  44.196 28.944 44.22 28.968 ;
      RECT  44.196 29.04 44.22 29.064 ;
    LAYER M5 ;
      RECT  33.072 44.196 33.096 44.24 ;
      RECT  33.168 44.196 33.192 44.24 ;
      RECT  33.264 44.196 33.288 44.24 ;
      RECT  33.36 44.196 33.384 44.24 ;
      RECT  33.456 44.196 33.48 44.24 ;
      RECT  33.552 44.196 33.576 44.24 ;
      RECT  33.648 44.196 33.672 44.24 ;
      RECT  33.744 44.196 33.768 44.24 ;
      RECT  33.84 44.196 33.864 44.24 ;
      RECT  33.936 44.196 33.96 44.24 ;
      RECT  34.032 44.196 34.056 44.24 ;
  END
END qfd_landh0d8n_107_EW_44x44
END LIBRARY
